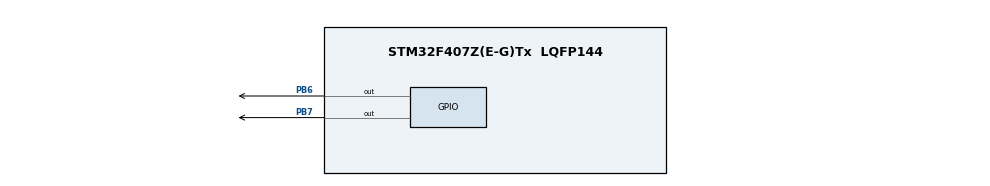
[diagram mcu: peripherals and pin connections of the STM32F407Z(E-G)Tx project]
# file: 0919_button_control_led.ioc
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Mcu.Family=STM32F4
Mcu.Name=STM32F407Z(E-G)Tx
Mcu.Package=LQFP144
NVIC.PriorityGroup=NVIC_PRIORITYGROUP_4
PA13.Mode=Serial_Wire
PA13.Signal=SYS_JTMS-SWDIO
PA14.Mode=Serial_Wire
PA14.Signal=SYS_JTCK-SWCLK
PB6.Signal=GPIO_Output
PB7.Signal=GPIO_Output
PH0-OSC_IN.Mode=HSE-External-Oscillator
PH0-OSC_IN.Signal=RCC_OSC_IN
PH1-OSC_OUT.Mode=HSE-External-Oscillator
PH1-OSC_OUT.Signal=RCC_OSC_OUT
ProjectManager.HeapSize=0x200
ProjectManager.StackSize=0x400
ProjectManager.TargetToolchain=CMake
RCC.48MHZClocksFreq_Value=84000000
RCC.AHBFreq_Value=168000000
RCC.APB1CLKDivider=RCC_HCLK_DIV4
RCC.APB1Freq_Value=42000000
RCC.APB1TimFreq_Value=84000000
RCC.APB2CLKDivider=RCC_HCLK_DIV2
RCC.APB2Freq_Value=84000000
RCC.APB2TimFreq_Value=168000000
RCC.CortexFreq_Value=168000000
RCC.HCLKFreq_Value=168000000
RCC.HSE_VALUE=8000000
RCC.HSI_VALUE=16000000
RCC.LSE_VALUE=32768
RCC.PLLM=4
RCC.PLLN=168
RCC.PLLSourceVirtual=RCC_PLLSOURCE_HSE
RCC.SYSCLKFreq_VALUE=168000000
RCC.SYSCLKSource=RCC_SYSCLKSOURCE_PLLCLK
RCC.VCOOutputFreq_Value=336000000
board=custom

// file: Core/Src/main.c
/* USER CODE BEGIN Header */
/**
  ******************************************************************************
  * @file           : main.c
  * @brief          : Main program body
  ******************************************************************************
  * @attention
  *
  * Copyright (c) 2025 STMicroelectronics.
  * All rights reserved.
  *
  * This software is licensed under terms that can be found in the LICENSE file
  * in the root directory of this software component.
  * If no LICENSE file comes with this software, it is provided AS-IS.
  *
  ******************************************************************************
  */
/* USER CODE END Header */
#include "main.h"

/* USER CODE BEGIN Includes */
#include "keys.h"
#include "oled.h"

/* USER CODE END Includes */

void SystemClock_Config(void);

/* USER CODE BEGIN 0 */
/*引脚配置*/
#define OLED_W_SCL(x)		HAL_GPIO_WritePin(GPIOB, GPIO_PIN_6, (GPIO_PinState)(x))
#define OLED_W_SDA(x)		HAL_GPIO_WritePin(GPIOB, GPIO_PIN_7, (GPIO_PinState)(x))

/*引脚初始化*/
void OLED_I2C_Init(void)
{
	__HAL_RCC_GPIOB_CLK_ENABLE();
	GPIO_InitTypeDef YuWei_GPIO_InitStructure;
 	YuWei_GPIO_InitStructure.Mode = GPIO_MODE_OUTPUT_OD;
	YuWei_GPIO_InitStructure.Speed = GPIO_SPEED_FREQ_HIGH;
	YuWei_GPIO_InitStructure.Pin = GPIO_PIN_6 | GPIO_PIN_7;
 	HAL_GPIO_Init(GPIOB, &YuWei_GPIO_InitStructure);
	OLED_W_SCL(1);
	OLED_W_SDA(1);
}

/*OLED字模库，宽8像素，高16像素*/
uint8_t OLED_F8x16[][16]=
{
	0x00,0x00,0x00,0x00,0x00,0x00,0x00,0x00,
	0x00,0x00,0x00,0x00,0x00,0x00,0x00,0x00,//  0

	0x00,0x00,0x00,0xF8,0x00,0x00,0x00,0x00,
	0x00,0x00,0x00,0x33,0x30,0x00,0x00,0x00,//! 1

	0x00,0x10,0x0C,0x06,0x10,0x0C,0x06,0x00,
	0x00,0x00,0x00,0x00,0x00,0x00,0x00,0x00,//" 2

	0x40,0xC0,0x78,0x40,0xC0,0x78,0x40,0x00,
	0x04,0x3F,0x04,0x04,0x3F,0x04,0x04,0x00,//# 3

	0x00,0x70,0x88,0xFC,0x08,0x30,0x00,0x00,
	0x00,0x18,0x20,0xFF,0x21,0x1E,0x00,0x00,//$ 4

	0xF0,0x08,0xF0,0x00,0xE0,0x18,0x00,0x00,
	0x00,0x21,0x1C,0x03,0x1E,0x21,0x1E,0x00,//% 5

	0x00,0xF0,0x08,0x88,0x70,0x00,0x00,0x00,
	0x1E,0x21,0x23,0x24,0x19,0x27,0x21,0x10,//& 6

	0x10,0x16,0x0E,0x00,0x00,0x00,0x00,0x00,
	0x00,0x00,0x00,0x00,0x00,0x00,0x00,0x00,//' 7

	0x00,0x00,0x00,0xE0,0x18,0x04,0x02,0x00,
	0x00,0x00,0x00,0x07,0x18,0x20,0x40,0x00,//( 8

	0x00,0x02,0x04,0x18,0xE0,0x00,0x00,0x00,
	0x00,0x40,0x20,0x18,0x07,0x00,0x00,0x00,//) 9

	0x40,0x40,0x80,0xF0,0x80,0x40,0x40,0x00,
	0x02,0x02,0x01,0x0F,0x01,0x02,0x02,0x00,//* 10

	0x00,0x00,0x00,0xF0,0x00,0x00,0x00,0x00,
	0x01,0x01,0x01,0x1F,0x01,0x01,0x01,0x00,//+ 11

	0x00,0x00,0x00,0x00,0x00,0x00,0x00,0x00,
	0x80,0xB0,0x70,0x00,0x00,0x00,0x00,0x00,//, 12

	0x00,0x00,0x00,0x00,0x00,0x00,0x00,0x00,
	0x00,0x01,0x01,0x01,0x01,0x01,0x01,0x01,//- 13

	0x00,0x00,0x00,0x00,0x00,0x00,0x00,0x00,
	0x00,0x30,0x30,0x00,0x00,0x00,0x00,0x00,//. 14

	0x00,0x00,0x00,0x00,0x80,0x60,0x18,0x04,
	0x00,0x60,0x18,0x06,0x01,0x00,0x00,0x00,/// 15

	0x00,0xE0,0x10,0x08,0x08,0x10,0xE0,0x00,
	0x00,0x0F,0x10,0x20,0x20,0x10,0x0F,0x00,//0 16

	0x00,0x10,0x10,0xF8,0x00,0x00,0x00,0x00,
	0x00,0x20,0x20,0x3F,0x20,0x20,0x00,0x00,//1 17

	0x00,0x70,0x08,0x08,0x08,0x88,0x70,0x00,
	0x00,0x30,0x28,0x24,0x22,0x21,0x30,0x00,//2 18

	0x00,0x30,0x08,0x88,0x88,0x48,0x30,0x00,
	0x00,0x18,0x20,0x20,0x20,0x11,0x0E,0x00,//3 19

	0x00,0x00,0xC0,0x20,0x10,0xF8,0x00,0x00,
	0x00,0x07,0x04,0x24,0x24,0x3F,0x24,0x00,//4 20

	0x00,0xF8,0x08,0x88,0x88,0x08,0x08,0x00,
	0x00,0x19,0x21,0x20,0x20,0x11,0x0E,0x00,//5 21

	0x00,0xE0,0x10,0x88,0x88,0x18,0x00,0x00,
	0x00,0x0F,0x11,0x20,0x20,0x11,0x0E,0x00,//6 22

	0x00,0x38,0x08,0x08,0xC8,0x38,0x08,0x00,
	0x00,0x00,0x00,0x3F,0x00,0x00,0x00,0x00,//7 23

	0x00,0x70,0x88,0x08,0x08,0x88,0x70,0x00,
	0x00,0x1C,0x22,0x21,0x21,0x22,0x1C,0x00,//8 24

	0x00,0xE0,0x10,0x08,0x08,0x10,0xE0,0x00,
	0x00,0x00,0x31,0x22,0x22,0x11,0x0F,0x00,//9 25

	0x00,0x00,0x00,0xC0,0xC0,0x00,0x00,0x00,
	0x00,0x00,0x00,0x30,0x30,0x00,0x00,0x00,//: 26

	0x00,0x00,0x00,0x80,0x00,0x00,0x00,0x00,
	0x00,0x00,0x80,0x60,0x00,0x00,0x00,0x00,//; 27

	0x00,0x00,0x80,0x40,0x20,0x10,0x08,0x00,
	0x00,0x01,0x02,0x04,0x08,0x10,0x20,0x00,//< 28

	0x40,0x40,0x40,0x40,0x40,0x40,0x40,0x00,
	0x04,0x04,0x04,0x04,0x04,0x04,0x04,0x00,//= 29

	0x00,0x08,0x10,0x20,0x40,0x80,0x00,0x00,
	0x00,0x20,0x10,0x08,0x04,0x02,0x01,0x00,//> 30

	0x00,0x70,0x48,0x08,0x08,0x08,0xF0,0x00,
	0x00,0x00,0x00,0x30,0x36,0x01,0x00,0x00,//? 31

	0xC0,0x30,0xC8,0x28,0xE8,0x10,0xE0,0x00,
	0x07,0x18,0x27,0x24,0x23,0x14,0x0B,0x00,//@ 32

	0x00,0x00,0xC0,0x38,0xE0,0x00,0x00,0x00,
	0x20,0x3C,0x23,0x02,0x02,0x27,0x38,0x20,//A 33

	0x08,0xF8,0x88,0x88,0x88,0x70,0x00,0x00,
	0x20,0x3F,0x20,0x20,0x20,0x11,0x0E,0x00,//B 34

	0xC0,0x30,0x08,0x08,0x08,0x08,0x38,0x00,
	0x07,0x18,0x20,0x20,0x20,0x10,0x08,0x00,//C 35

	0x08,0xF8,0x08,0x08,0x08,0x10,0xE0,0x00,
	0x20,0x3F,0x20,0x20,0x20,0x10,0x0F,0x00,//D 36

	0x08,0xF8,0x88,0x88,0xE8,0x08,0x10,0x00,
	0x20,0x3F,0x20,0x20,0x23,0x20,0x18,0x00,//E 37

	0x08,0xF8,0x88,0x88,0xE8,0x08,0x10,0x00,
	0x20,0x3F,0x20,0x00,0x03,0x00,0x00,0x00,//F 38

	0xC0,0x30,0x08,0x08,0x08,0x38,0x00,0x00,
	0x07,0x18,0x20,0x20,0x22,0x1E,0x02,0x00,//G 39

	0x08,0xF8,0x08,0x00,0x00,0x08,0xF8,0x08,
	0x20,0x3F,0x21,0x01,0x01,0x21,0x3F,0x20,//H 40

	0x00,0x08,0x08,0xF8,0x08,0x08,0x00,0x00,
	0x00,0x20,0x20,0x3F,0x20,0x20,0x00,0x00,//I 41

	0x00,0x00,0x08,0x08,0xF8,0x08,0x08,0x00,
	0xC0,0x80,0x80,0x80,0x7F,0x00,0x00,0x00,//J 42

	0x08,0xF8,0x88,0xC0,0x28,0x18,0x08,0x00,
	0x20,0x3F,0x20,0x01,0x26,0x38,0x20,0x00,//K 43

	0x08,0xF8,0x08,0x00,0x00,0x00,0x00,0x00,
	0x20,0x3F,0x20,0x20,0x20,0x20,0x30,0x00,//L 44

	0x08,0xF8,0xF8,0x00,0xF8,0xF8,0x08,0x00,
	0x20,0x3F,0x00,0x3F,0x00,0x3F,0x20,0x00,//M 45

	0x08,0xF8,0x30,0xC0,0x00,0x08,0xF8,0x08,
	0x20,0x3F,0x20,0x00,0x07,0x18,0x3F,0x00,//N 46

	0xE0,0x10,0x08,0x08,0x08,0x10,0xE0,0x00,
	0x0F,0x10,0x20,0x20,0x20,0x10,0x0F,0x00,//O 47

	0x08,0xF8,0x08,0x08,0x08,0x08,0xF0,0x00,
	0x20,0x3F,0x21,0x01,0x01,0x01,0x00,0x00,//P 48

	0xE0,0x10,0x08,0x08,0x08,0x10,0xE0,0x00,
	0x0F,0x18,0x24,0x24,0x38,0x50,0x4F,0x00,//Q 49

	0x08,0xF8,0x88,0x88,0x88,0x88,0x70,0x00,
	0x20,0x3F,0x20,0x00,0x03,0x0C,0x30,0x20,//R 50

	0x00,0x70,0x88,0x08,0x08,0x08,0x38,0x00,
	0x00,0x38,0x20,0x21,0x21,0x22,0x1C,0x00,//S 51

	0x18,0x08,0x08,0xF8,0x08,0x08,0x18,0x00,
	0x00,0x00,0x20,0x3F,0x20,0x00,0x00,0x00,//T 52

	0x08,0xF8,0x08,0x00,0x00,0x08,0xF8,0x08,
	0x00,0x1F,0x20,0x20,0x20,0x20,0x1F,0x00,//U 53

	0x08,0x78,0x88,0x00,0x00,0xC8,0x38,0x08,
	0x00,0x00,0x07,0x38,0x0E,0x01,0x00,0x00,//V 54

	0xF8,0x08,0x00,0xF8,0x00,0x08,0xF8,0x00,
	0x03,0x3C,0x07,0x00,0x07,0x3C,0x03,0x00,//W 55

	0x08,0x18,0x68,0x80,0x80,0x68,0x18,0x08,
	0x20,0x30,0x2C,0x03,0x03,0x2C,0x30,0x20,//X 56

	0x08,0x38,0xC8,0x00,0xC8,0x38,0x08,0x00,
	0x00,0x00,0x20,0x3F,0x20,0x00,0x00,0x00,//Y 57

	0x10,0x08,0x08,0x08,0xC8,0x38,0x08,0x00,
	0x20,0x38,0x26,0x21,0x20,0x20,0x18,0x00,//Z 58

	0x00,0x00,0x00,0xFE,0x02,0x02,0x02,0x00,
	0x00,0x00,0x00,0x7F,0x40,0x40,0x40,0x00,//[ 59

	0x00,0x0C,0x30,0xC0,0x00,0x00,0x00,0x00,
	0x00,0x00,0x00,0x01,0x06,0x38,0xC0,0x00,//\ 60

	0x00,0x02,0x02,0x02,0xFE,0x00,0x00,0x00,
	0x00,0x40,0x40,0x40,0x7F,0x00,0x00,0x00,//] 61

	0x00,0x00,0x04,0x02,0x02,0x02,0x04,0x00,
	0x00,0x00,0x00,0x00,0x00,0x00,0x00,0x00,//^ 62

	0x00,0x00,0x00,0x00,0x00,0x00,0x00,0x00,
	0x80,0x80,0x80,0x80,0x80,0x80,0x80,0x80,//_ 63

	0x00,0x02,0x02,0x04,0x00,0x00,0x00,0x00,
	0x00,0x00,0x00,0x00,0x00,0x00,0x00,0x00,//` 64

	0x00,0x00,0x80,0x80,0x80,0x80,0x00,0x00,
	0x00,0x19,0x24,0x22,0x22,0x22,0x3F,0x20,//a 65

	0x08,0xF8,0x00,0x80,0x80,0x00,0x00,0x00,
	0x00,0x3F,0x11,0x20,0x20,0x11,0x0E,0x00,//b 66

	0x00,0x00,0x00,0x80,0x80,0x80,0x00,0x00,
	0x00,0x0E,0x11,0x20,0x20,0x20,0x11,0x00,//c 67

	0x00,0x00,0x00,0x80,0x80,0x88,0xF8,0x00,
	0x00,0x0E,0x11,0x20,0x20,0x10,0x3F,0x20,//d 68

	0x00,0x00,0x80,0x80,0x80,0x80,0x00,0x00,
	0x00,0x1F,0x22,0x22,0x22,0x22,0x13,0x00,//e 69

	0x00,0x80,0x80,0xF0,0x88,0x88,0x88,0x18,
	0x00,0x20,0x20,0x3F,0x20,0x20,0x00,0x00,//f 70

	0x00,0x00,0x80,0x80,0x80,0x80,0x80,0x00,
	0x00,0x6B,0x94,0x94,0x94,0x93,0x60,0x00,//g 71

	0x08,0xF8,0x00,0x80,0x80,0x80,0x00,0x00,
	0x20,0x3F,0x21,0x00,0x00,0x20,0x3F,0x20,//h 72

	0x00,0x80,0x98,0x98,0x00,0x00,0x00,0x00,
	0x00,0x20,0x20,0x3F,0x20,0x20,0x00,0x00,//i 73

	0x00,0x00,0x00,0x80,0x98,0x98,0x00,0x00,
	0x00,0xC0,0x80,0x80,0x80,0x7F,0x00,0x00,//j 74

	0x08,0xF8,0x00,0x00,0x80,0x80,0x80,0x00,
	0x20,0x3F,0x24,0x02,0x2D,0x30,0x20,0x00,//k 75

	0x00,0x08,0x08,0xF8,0x00,0x00,0x00,0x00,
	0x00,0x20,0x20,0x3F,0x20,0x20,0x00,0x00,//l 76

	0x80,0x80,0x80,0x80,0x80,0x80,0x80,0x00,
	0x20,0x3F,0x20,0x00,0x3F,0x20,0x00,0x3F,//m 77

	0x80,0x80,0x00,0x80,0x80,0x80,0x00,0x00,
	0x20,0x3F,0x21,0x00,0x00,0x20,0x3F,0x20,//n 78

	0x00,0x00,0x80,0x80,0x80,0x80,0x00,0x00,
	0x00,0x1F,0x20,0x20,0x20,0x20,0x1F,0x00,//o 79

	0x80,0x80,0x00,0x80,0x80,0x00,0x00,0x00,
	0x80,0xFF,0xA1,0x20,0x20,0x11,0x0E,0x00,//p 80

	0x00,0x00,0x00,0x80,0x80,0x80,0x80,0x00,
	0x00,0x0E,0x11,0x20,0x20,0xA0,0xFF,0x80,//q 81

	0x80,0x80,0x80,0x00,0x80,0x80,0x80,0x00,
	0x20,0x20,0x3F,0x21,0x20,0x00,0x01,0x00,//r 82

	0x00,0x00,0x80,0x80,0x80,0x80,0x80,0x00,
	0x00,0x33,0x24,0x24,0x24,0x24,0x19,0x00,//s 83

	0x00,0x80,0x80,0xE0,0x80,0x80,0x00,0x00,
	0x00,0x00,0x00,0x1F,0x20,0x20,0x00,0x00,//t 84

	0x80,0x80,0x00,0x00,0x00,0x80,0x80,0x00,
	0x00,0x1F,0x20,0x20,0x20,0x10,0x3F,0x20,//u 85

	0x80,0x80,0x80,0x00,0x00,0x80,0x80,0x80,
	0x00,0x01,0x0E,0x30,0x08,0x06,0x01,0x00,//v 86

	0x80,0x80,0x00,0x80,0x00,0x80,0x80,0x80,
	0x0F,0x30,0x0C,0x03,0x0C,0x30,0x0F,0x00,//w 87

	0x00,0x80,0x80,0x00,0x80,0x80,0x80,0x00,
	0x00,0x20,0x31,0x2E,0x0E,0x31,0x20,0x00,//x 88

	0x80,0x80,0x80,0x00,0x00,0x80,0x80,0x80,
	0x80,0x81,0x8E,0x70,0x18,0x06,0x01,0x00,//y 89

	0x00,0x80,0x80,0x80,0x80,0x80,0x80,0x00,
	0x00,0x21,0x30,0x2C,0x22,0x21,0x30,0x00,//z 90

	0x00,0x00,0x00,0x00,0x80,0x7C,0x02,0x02,
	0x00,0x00,0x00,0x00,0x00,0x3F,0x40,0x40,//{ 91

	0x00,0x00,0x00,0x00,0xFF,0x00,0x00,0x00,
	0x00,0x00,0x00,0x00,0xFF,0x00,0x00,0x00,//| 92

	0x00,0x02,0x02,0x7C,0x80,0x00,0x00,0x00,
	0x00,0x40,0x40,0x3F,0x00,0x00,0x00,0x00,//} 93

	0x00,0x06,0x01,0x01,0x02,0x02,0x04,0x04,
	0x00,0x00,0x00,0x00,0x00,0x00,0x00,0x00,//~ 94
};

/**
  * @brief  I2C开始
  * @param  无
  * @retval 无
  */
void OLED_I2C_Start(void)
{
	OLED_W_SDA(1);
	OLED_W_SCL(1);
	OLED_W_SDA(0);
	OLED_W_SCL(0);
}

/**
  * @brief  I2C停止
  * @param  无
  * @retval 无
  */
void OLED_I2C_Stop(void)
{
	OLED_W_SDA(0);
	OLED_W_SCL(1);
	OLED_W_SDA(1);
}

/**
  * @brief  I2C发送一个字节
  * @param  Byte 要发送的一个字节
  * @retval 无
  */
void OLED_I2C_SendByte(uint8_t Byte)
{
	uint8_t i;
	for (i = 0; i < 8; i++)
	{
		OLED_W_SDA(Byte & (0x80 >> i));
		OLED_W_SCL(1);
		OLED_W_SCL(0);
	}
	OLED_W_SCL(1);	//额外的一个时钟，不处理应答信号
	OLED_W_SCL(0);
}

/**
  * @brief  OLED写命令
  * @param  Command 要写入的命令
  * @retval 无
  */
void OLED_WriteCommand(uint8_t Command)
{
	OLED_I2C_Start();
	OLED_I2C_SendByte(0x78);		//从机地址
	OLED_I2C_SendByte(0x00);		//写命令
	OLED_I2C_SendByte(Command);
	OLED_I2C_Stop();
}

/**
  * @brief  OLED写数据
  * @param  Data 要写入的数据
  * @retval 无
  */
void OLED_WriteData(uint8_t Data)
{
	OLED_I2C_Start();
	OLED_I2C_SendByte(0x78);		//从机地址
	OLED_I2C_SendByte(0x40);		//写数据
	OLED_I2C_SendByte(Data);
	OLED_I2C_Stop();
}

/**
  * @brief  OLED设置光标位置
  * @param  Y 以左上角为原点，向下方向的坐标，范围：0~7
  * @param  X 以左上角为原点，向右方向的坐标，范围：0~127
  * @retval 无
  */
void OLED_SetCursor(uint8_t Y, uint8_t X)
{
	OLED_WriteCommand(0xB0 | Y);					//设置Y位置
	OLED_WriteCommand(0x10 | ((X & 0xF0) >> 4));	//设置X位置低4位
	OLED_WriteCommand(0x00 | (X & 0x0F));			//设置X位置高4位
}

/**
  * @brief  OLED清屏
  * @param  无
  * @retval 无
  */
void OLED_Clear(void)
{
	uint8_t i, j;
	for (j = 0; j < 8; j++)
	{
		OLED_SetCursor(j, 0);
		for(i = 0; i < 128; i++)
		{
			OLED_WriteData(0x00);
		}
	}
}

/**
  * @brief  OLED显示一个字符
  * @param  Row 行位置，范围：1~4
  * @param  Column 列位置，范围：1~16
  * @param  Character 要显示的一个字符，范围：ASCII可见字符
  * @retval 无
  */
void OLED_ShowCharacter(uint8_t Row, uint8_t Column, char Character)
{
	uint8_t i;
	OLED_SetCursor((Row - 1) * 2, (Column - 1) * 8);			//设置光标位置在上半部分
	for (i = 0; i < 8; i++)
	{
		OLED_WriteData(OLED_F8x16[Character - ' '][i]);			//显示上半部分内容
	}
	OLED_SetCursor((Row - 1) * 2 + 1, (Column - 1) * 8);		//设置光标位置在下半部分
	for (i = 0; i < 8; i++)
	{
		OLED_WriteData(OLED_F8x16[Character - ' '][i + 8]);		//显示下半部分内容
	}
}

/**
  * @brief  OLED显示字符串
  * @param  Row 起始行位置，范围：1~4
  * @param  Column 起始列位置，范围：1~16
  * @param  String 要显示的字符串，范围：ASCII可见字符
  * @retval 无
  */
void OLED_ShowString(uint8_t Row, uint8_t Column, char *String)
{
	uint8_t i;
	for (i = 0; String[i] != '\0'; i++)
	{
		OLED_ShowCharacter(Row, Column + i, String[i]);
	}
}

typedef struct
{
	char Index[3];
	char Mask[32];
}GB16;

//宋体
//16*16大小
//逐行式，顺向（高位在前）
const GB16 OLED_F16x16[] =
{
	"余",0x80,0x80,0x40,0x20,0x50,0x48,0x44,0xC3,0x44,0x48,0x50,0x20,0x40,0x80,0x80,0x00,0x00,0x40,0x22,0x1A,0x02,0x42,0x82,0x7F,0x02,0x02,0x02,0x0A,0x12,0x60,0x00,0x00,
	"伟",0x00,0x80,0x60,0xF8,0x07,0x08,0x48,0x48,0x48,0xFF,0x48,0x48,0x48,0x48,0x08,0x00,0x01,0x00,0x00,0xFF,0x00,0x02,0x02,0x02,0x02,0xFF,0x02,0x02,0x12,0x22,0x1E,0x00,
	"●",0x00,0xE0,0xF8,0xFC,0xFC,0xFE,0xFE,0xFE,0xFE,0xFE,0xFC,0xFC,0xF8,0xE0,0x00,0x00,0x00,0x03,0x0F,0x1F,0x1F,0x3F,0x3F,0x3F,0x3F,0x3F,0x1F,0x1F,0x0F,0x03,0x00,0x00,
	"○",0x00,0xE0,0xF8,0x1C,0x04,0x06,0x02,0x02,0x02,0x06,0x04,0x1C,0xF8,0xE0,0x00,0x00,0x00,0x03,0x0F,0x1C,0x10,0x30,0x20,0x20,0x20,0x30,0x10,0x1C,0x0F,0x03,0x00,0x00,
	"·",0x00,0x00,0x00,0x00,0x00,0x00,0x00,0x00,0x00,0x00,0x00,0x00,0x00,0x00,0x00,0x00,0x00,0x00,0x00,0x00,0x00,0x00,0x00,0x03,0x03,0x00,0x00,0x00,0x00,0x00,0x00,0x00,
	"→",0x80,0x80,0x80,0x80,0x80,0x80,0x80,0x80,0x90,0xA0,0xE0,0xC0,0xC0,0x80,0x80,0x00,0x00,0x00,0x00,0x00,0x00,0x00,0x00,0x00,0x04,0x02,0x03,0x01,0x01,0x00,0x00,0x00,
	"省",0x00,0x10,0x88,0x86,0xC0,0xC0,0xA0,0xAF,0x90,0x90,0x88,0x82,0x84,0x08,0x00,0x00,0x01,0x01,0x00,0xFF,0x4A,0x4A,0x4A,0x4A,0x4A,0x4A,0x4A,0x4A,0xFF,0x00,0x00,0x00,
	"市",0x00,0x08,0x88,0x88,0x88,0x88,0x89,0xFA,0x88,0x88,0x88,0x88,0x88,0x08,0x00,0x00,0x00,0x00,0x3F,0x00,0x00,0x00,0x00,0xFF,0x00,0x00,0x10,0x20,0x1F,0x00,0x00,0x00,
	"·",0x00,0x00,0x00,0x00,0x00,0x00,0x00,0x00,0x00,0x00,0x00,0x00,0x00,0x00,0x00,0x00,0x00,0x00,0x00,0x00,0x00,0x00,0x00,0x03,0x03,0x00,0x00,0x00,0x00,0x00,0x00,0x00,
	"°",0x00,0x00,0x0C,0x12,0x12,0x0C,0x00,0x00,0x00,0x00,0x00,0x00,0x00,0x00,0x00,0x00,0x00,0x00,0x00,0x00,0x00,0x00,0x00,0x00,0x00,0x00,0x00,0x00,0x00,0x00,0x00,0x00,
	"…",0x00,0xC0,0xC0,0x00,0x00,0x00,0xC0,0xC0,0x00,0x00,0x00,0xC0,0xC0,0x00,0x00,0x00,0x00,0x00,0x00,0x00,0x00,0x00,0x00,0x00,0x00,0x00,0x00,0x00,0x00,0x00,0x00,0x00,
	"：",0x00,0x00,0x00,0x00,0x00,0x00,0x00,0x00,0x00,0x00,0x00,0x00,0x00,0x00,0x00,0x00,0x00,0x00,0x36,0x36,0x00,0x00,0x00,0x00,0x00,0x00,0x00,0x00,0x00,0x00,0x00,0x00,
	"℃",0x06,0x09,0x09,0xE6,0xF8,0x0C,0x04,0x02,0x02,0x02,0x02,0x02,0x04,0x1E,0x00,0x00,0x00,0x00,0x00,0x07,0x1F,0x30,0x20,0x40,0x40,0x40,0x40,0x40,0x20,0x10,0x00,0x00,
	"％",0x00,0x00,0x7C,0x82,0x82,0x7C,0x00,0x80,0x40,0x20,0x10,0x08,0x04,0x02,0x00,0x00,0x00,0x20,0x10,0x08,0x04,0x02,0x01,0x00,0x3E,0x41,0x41,0x3E,0x00,0x00,0x00,0x00,
	"㎡",0x00,0x10,0xE0,0x10,0x10,0xE0,0x10,0x10,0xE0,0x00,0x44,0x62,0x52,0x4C,0x00,0x00,0x00,0x00,0x0F,0x00,0x00,0x0F,0x00,0x00,0x0F,0x00,0x00,0x00,0x00,0x00,0x00,0x00,
		"陈",0x40,0x40,0x42,0xCC,0x00,0x50,0x4E,0xC8,0x48,0x7F,0xC8,0x48,0x48,0x40,0x00,0x00,0x00,0x40,0x20,0x1F,0x20,0x50,0x4C,0x43,0x40,0x40,0x4F,0x50,0x50,0x5C,0x40,0x00,
	"选",0x40,0x21,0x11,0x09,0x7D,0x4B,0x49,0x49,0x49,0x49,0x49,0x79,0x01,0x01,0x00,0x00,0x10,0x09,0xFD,0x4B,0x49,0x49,0xF9,0x10,0x09,0xFD,0x4B,0x49,0x49,0xF9,0x01,0x00,
	"磊",0x06,0x09,0x09,0xE6,0xF8,0x0C,0x04,0x02,0x02,0x02,0x02,0x02,0x04,0x1E,0x00,0x00,0x00,0x00,0x00,0x07,0x1F,0x30,0x20,0x40,0x40,0x40,0x40,0x40,0x20,0x10,0x00,0x00,
	"大",0x20,0x20,0x20,0x20,0x20,0x20,0x20,0xFF,0x20,0x20,0x20,0x20,0x20,0x20,0x20,0x00,0x80,0x80,0x40,0x20,0x10,0x0C,0x03,0x00,0x03,0x0C,0x10,0x20,0x40,0x80,0x80,0x00,/*"大",0*/
	"气",0x20,0x10,0x4C,0x47,0x54,0x54,0x54,0x54,0x54,0x54,0x54,0xD4,0x04,0x04,0x00,0x00,0x00,0x00,0x00,0x00,0x00,0x00,0x00,0x00,0x00,0x00,0x00,0x0F,0x30,0x40,0xF0,0x00,/*"气",1*/
	"温",0x10,0x60,0x02,0x8C,0x00,0x00,0xFE,0x92,0x92,0x92,0x92,0x92,0xFE,0x00,0x00,0x00,0x04,0x04,0x7E,0x01,0x40,0x7E,0x42,0x42,0x7E,0x42,0x7E,0x42,0x42,0x7E,0x40,0x00,/*"温",2*/
	"湿",0x10,0x60,0x02,0x8C,0x00,0xFE,0x92,0x92,0x92,0x92,0x92,0x92,0xFE,0x00,0x00,0x00,0x04,0x04,0x7E,0x01,0x44,0x48,0x50,0x7F,0x40,0x40,0x7F,0x50,0x48,0x44,0x40,0x00,/*"湿",3*/
	"度",0x00,0x00,0xFC,0x24,0x24,0x24,0xFC,0x25,0x26,0x24,0xFC,0x24,0x24,0x24,0x04,0x00,0x40,0x30,0x8F,0x80,0x84,0x4C,0x55,0x25,0x25,0x25,0x55,0x4C,0x80,0x80,0x80,0x00,/*"度",4*/
	"光",0x40,0x40,0x42,0x44,0x58,0xC0,0x40,0x7F,0x40,0xC0,0x50,0x48,0x46,0x40,0x40,0x00,0x80,0x80,0x40,0x20,0x18,0x07,0x00,0x00,0x00,0x3F,0x40,0x40,0x40,0x40,0x78,0x00,/*"光",5*/
	"照",0x00,0xFE,0x42,0x42,0x42,0xFE,0x00,0x42,0xA2,0x9E,0x82,0xA2,0xC2,0xBE,0x00,0x00,0x80,0x6F,0x08,0x08,0x28,0xCF,0x00,0x00,0x2F,0xC8,0x08,0x08,0x28,0xCF,0x00,0x00,/*"照",6*/
	"强",0x02,0xE2,0x22,0x22,0x3E,0x00,0x80,0x9E,0x92,0x92,0xF2,0x92,0x92,0x9E,0x80,0x00,0x00,0x43,0x82,0x42,0x3E,0x40,0x47,0x44,0x44,0x44,0x7F,0x44,0x44,0x54,0xE7,0x00,/*"强",7*/
	"度",0x00,0x00,0xFC,0x24,0x24,0x24,0xFC,0x25,0x26,0x24,0xFC,0x24,0x24,0x24,0x04,0x00,0x40,0x30,0x8F,0x80,0x84,0x4C,0x55,0x25,0x25,0x25,0x55,0x4C,0x80,0x80,0x80,0x00,/*"度",8*/
	"紫",0x20,0x20,0x3E,0x20,0x1F,0x94,0x54,0x00,0x1F,0x24,0xA4,0x24,0x22,0x38,0x00,0x00,0x00,0x80,0x48,0x29,0x09,0x4D,0x8D,0x7B,0x0B,0x09,0x28,0x4C,0x98,0x00,0x00,0x00,/*"紫",9*/
	"外",0x00,0xC0,0x30,0x1F,0x10,0x10,0xF0,0x00,0x00,0xFF,0x20,0x40,0x80,0x00,0x00,0x00,0x81,0x40,0x21,0x12,0x0C,0x03,0x00,0x00,0x00,0xFF,0x00,0x00,0x00,0x03,0x00,0x00,/*"外",10*/
	"线",0x20,0x30,0xAC,0x63,0x20,0x18,0x80,0x90,0x90,0xFF,0x90,0x49,0x4A,0x48,0x40,0x00,0x22,0x67,0x22,0x12,0x12,0x12,0x40,0x40,0x20,0x13,0x0C,0x14,0x22,0x41,0xF8,0x00,/*"线",11*/
	"线",0x20,0x30,0xAC,0x63,0x20,0x18,0x80,0x90,0x90,0xFF,0x90,0x49,0x4A,0x48,0x40,0x00,0x22,0x67,0x22,0x12,0x12,0x12,0x40,0x40,0x20,0x13,0x0C,0x14,0x22,0x41,0xF8,0x00,/*"线",12*/
	"加",0x10,0x10,0x10,0xFF,0x10,0x10,0xF0,0x00,0x00,0xF8,0x08,0x08,0x08,0xF8,0x00,0x00,0x80,0x40,0x30,0x0F,0x40,0x80,0x7F,0x00,0x00,0x7F,0x20,0x20,0x20,0x7F,0x00,0x00,/*"加",13*/
	"轴",0xC8,0xB8,0x8F,0xE8,0x88,0x88,0x00,0xF0,0x10,0x10,0xFF,0x10,0x10,0xF0,0x00,0x00,0x08,0x18,0x08,0xFF,0x04,0x04,0x00,0xFF,0x42,0x42,0x7F,0x42,0x42,0xFF,0x00,0x00,/*"轴",14*/
	"速",0x40,0x40,0x42,0xCC,0x00,0x04,0xF4,0x94,0x94,0xFF,0x94,0x94,0xF4,0x04,0x00,0x00,0x00,0x40,0x20,0x1F,0x20,0x48,0x44,0x42,0x41,0x5F,0x41,0x42,0x44,0x48,0x40,0x00,/*"速",15*/
	"度",0x00,0x00,0xFC,0x24,0x24,0x24,0xFC,0x25,0x26,0x24,0xFC,0x24,0x24,0x24,0x04,0x00,0x40,0x30,0x8F,0x80,0x84,0x4C,0x55,0x25,0x25,0x25,0x55,0x4C,0x80,0x80,0x80,0x00,/*"度",16*/
	"姿",0x20,0x21,0xF2,0x08,0x04,0x10,0x88,0x84,0x47,0x34,0x44,0x84,0x94,0x0C,0x00,0x00,0x04,0x84,0x85,0x94,0x5D,0x57,0x24,0x24,0x24,0x54,0x4C,0x44,0x84,0x05,0x05,0x00,/*"姿",17*/
	"态",0x00,0x04,0x84,0x84,0x44,0x24,0x54,0x8F,0x14,0x24,0x44,0x84,0x84,0x04,0x00,0x00,0x41,0x39,0x00,0x00,0x3C,0x40,0x40,0x42,0x4C,0x40,0x40,0x70,0x04,0x09,0x31,0x00,/*"态",18*/
	"角",0x20,0x10,0xE8,0x24,0x27,0x24,0x24,0xE4,0x24,0x34,0x2C,0x20,0xE0,0x00,0x00,0x00,0x80,0x60,0x1F,0x09,0x09,0x09,0x09,0x7F,0x09,0x09,0x49,0x89,0x7F,0x00,0x00,0x00,/*"角",19*/
	"欧",0x00,0xFE,0x12,0x22,0xC2,0x3A,0x02,0x40,0x30,0x0F,0xC8,0x08,0x28,0x18,0x00,0x00,0x00,0x3F,0x24,0x23,0x20,0x27,0xA0,0x40,0x30,0x0E,0x01,0x0E,0x30,0x40,0x80,0x00,/*"欧",20*/
	"拉",0x10,0x10,0x10,0xFF,0x90,0x40,0x10,0x90,0x10,0x11,0x16,0x10,0x10,0xD0,0x10,0x00,0x02,0x42,0x81,0x7F,0x00,0x40,0x40,0x41,0x5E,0x40,0x40,0x70,0x4E,0x41,0x40,0x00,/*"拉",21*/
	"四",0x00,0xFC,0x04,0x04,0x04,0xFC,0x04,0x04,0x04,0xFC,0x04,0x04,0x04,0xFC,0x00,0x00,0x00,0x7F,0x28,0x24,0x23,0x20,0x20,0x20,0x20,0x21,0x22,0x22,0x22,0x7F,0x00,0x00,/*"四",22*/
	"元",0x20,0x20,0x22,0x22,0x22,0xE2,0x22,0x22,0x22,0xE2,0x22,0x22,0x22,0x20,0x20,0x00,0x80,0x40,0x20,0x10,0x0C,0x03,0x00,0x00,0x00,0x3F,0x40,0x40,0x40,0x40,0x78,0x00,/*"元",23*/
	"数",0x90,0x52,0x34,0x10,0xFF,0x10,0x34,0x52,0x80,0x70,0x8F,0x08,0x08,0xF8,0x08,0x00,0x82,0x9A,0x56,0x63,0x22,0x52,0x8E,0x00,0x80,0x40,0x33,0x0C,0x33,0x40,0x80,0x00,/*"数",24*/
	"俯",0x80,0x60,0xF8,0x07,0x00,0xFC,0x04,0xC4,0x34,0x85,0x86,0x84,0xF4,0x84,0x84,0x00,0x00,0x00,0xFF,0x40,0x30,0x0F,0x01,0xFF,0x00,0x02,0x4C,0x80,0x7F,0x00,0x00,0x00,/*"俯",25*/
	"仰",0x00,0x80,0x60,0xF8,0x07,0x00,0xFC,0x04,0x02,0x00,0xFC,0x04,0x04,0xFC,0x00,0x00,0x01,0x00,0x00,0xFF,0x00,0x00,0x1F,0x08,0x04,0x00,0xFF,0x04,0x08,0x07,0x00,0x00,/*"仰",26*/
	"翻",0x96,0x5A,0x32,0x7E,0x31,0x59,0x95,0x12,0x22,0xFE,0x00,0x12,0x22,0xFE,0x00,0x00,0x00,0xFF,0x49,0x7F,0x49,0xFF,0x00,0x44,0x82,0x7F,0x04,0x42,0x81,0x7F,0x00,0x00,/*"翻",27*/
	"滚",0x10,0x60,0x02,0x8C,0x00,0x24,0x94,0xCC,0xA5,0x96,0xC4,0x8C,0x14,0x24,0x00,0x00,0x04,0x04,0x7E,0x01,0x20,0x10,0x08,0xFC,0x42,0x24,0x08,0x15,0x22,0x40,0x40,0x00,/*"滚",0*/
	"偏",0x80,0x60,0xF8,0x07,0x00,0xFC,0x24,0x24,0x25,0x26,0x24,0x24,0x24,0x3C,0x00,0x00,0x00,0x00,0xFF,0x40,0x3C,0x03,0xFF,0x09,0x7F,0x09,0x7F,0x09,0x89,0xFF,0x00,0x00,/*"偏",1*/
	"航",0x80,0xFC,0x96,0xE5,0x84,0xFC,0x00,0x08,0xC8,0x49,0x4A,0xC8,0x08,0x08,0x00,0x00,0x80,0x7F,0x02,0x4C,0x80,0x7F,0x80,0x60,0x1F,0x00,0x00,0x3F,0x40,0x40,0x78,0x00,/*"航",2*/
	"正",0x00,0x02,0x02,0xC2,0x02,0x02,0x02,0xFE,0x82,0x82,0x82,0x82,0x82,0x02,0x00,0x00,0x40,0x40,0x40,0x7F,0x40,0x40,0x40,0x7F,0x40,0x40,0x40,0x40,0x40,0x40,0x40,0x00,/*"正",3*/
	"在",0x08,0x08,0x88,0xC8,0x38,0x0C,0x0B,0x08,0x08,0xE8,0x08,0x08,0x08,0x08,0x08,0x00,0x02,0x01,0x00,0xFF,0x40,0x41,0x41,0x41,0x41,0x7F,0x41,0x41,0x41,0x41,0x40,0x00,/*"在",4*/
	"初",0x08,0x08,0x89,0xEA,0x18,0x88,0x00,0x04,0x04,0xFC,0x04,0x04,0x04,0xFC,0x00,0x00,0x02,0x01,0x00,0xFF,0x01,0x86,0x40,0x20,0x18,0x07,0x40,0x80,0x40,0x3F,0x00,0x00,/*"初",5*/
	"始",0x10,0x10,0xF0,0x1F,0x10,0xF0,0x00,0x40,0xE0,0x58,0x47,0x40,0x50,0x60,0xC0,0x00,0x40,0x22,0x15,0x08,0x16,0x21,0x00,0x00,0xFE,0x42,0x42,0x42,0x42,0xFE,0x00,0x00,/*"始",6*/
	"化",0x00,0x80,0x60,0xF8,0x07,0x00,0x00,0x00,0xFF,0x40,0x20,0x10,0x08,0x04,0x00,0x00,0x01,0x00,0x00,0xFF,0x00,0x04,0x02,0x01,0x3F,0x40,0x40,0x40,0x40,0x40,0x78,0x00,/*"化",7*/
	"中",0x00,0x00,0xF0,0x10,0x10,0x10,0x10,0xFF,0x10,0x10,0x10,0x10,0xF0,0x00,0x00,0x00,0x00,0x00,0x0F,0x04,0x04,0x04,0x04,0xFF,0x04,0x04,0x04,0x04,0x0F,0x00,0x00,0x00,/*"中",8*/
	"毕",0x00,0x00,0xFF,0x88,0x88,0x48,0x48,0x00,0x7F,0x88,0x84,0x84,0x82,0xE0,0x00,0x00,0x04,0x04,0x05,0x04,0x04,0x04,0x04,0xFF,0x04,0x04,0x04,0x04,0x04,0x04,0x04,0x00,/*"毕",9*/
	"向",0x00,0xF8,0x08,0x08,0x0C,0xCA,0x49,0x48,0x48,0xC8,0x08,0x08,0x08,0xF8,0x00,0x00,0x00,0xFF,0x00,0x00,0x00,0x1F,0x08,0x08,0x08,0x1F,0x00,0x40,0x80,0x7F,0x00,0x00,/*"向",10*/
	"上",0x00,0x00,0x00,0x00,0x00,0x00,0xFF,0x40,0x40,0x40,0x40,0x40,0x40,0x00,0x00,0x00,0x40,0x40,0x40,0x40,0x40,0x40,0x7F,0x40,0x40,0x40,0x40,0x40,0x40,0x40,0x40,0x00,/*"上",11*/
	"下",0x02,0x02,0x02,0x02,0x02,0x02,0xFE,0x02,0x02,0x42,0x82,0x02,0x02,0x02,0x02,0x00,0x00,0x00,0x00,0x00,0x00,0x00,0xFF,0x00,0x00,0x00,0x00,0x01,0x06,0x00,0x00,0x00,/*"下",12*/
	"左",0x08,0x08,0x08,0x08,0x88,0x78,0x0F,0x08,0x08,0x08,0x08,0x08,0x08,0x08,0x08,0x00,0x20,0x10,0x48,0x46,0x41,0x41,0x41,0x41,0x7F,0x41,0x41,0x41,0x41,0x40,0x40,0x00,/*"左",13*/
	"右",0x08,0x08,0x08,0x08,0xC8,0x38,0x0F,0x08,0x08,0x08,0x08,0x08,0x08,0x08,0x08,0x00,0x08,0x04,0x02,0x01,0xFF,0x41,0x41,0x41,0x41,0x41,0x41,0x41,0xFF,0x00,0x00,0x00,/*"右",14*/
	"前",0x08,0x08,0xE8,0x29,0x2E,0x28,0xE8,0x08,0x08,0xC8,0x0C,0x0B,0xE8,0x08,0x08,0x00,0x00,0x00,0xFF,0x09,0x49,0x89,0x7F,0x00,0x00,0x0F,0x40,0x80,0x7F,0x00,0x00,0x00,/*"前",15*/
	"后",0x00,0x00,0x00,0xFC,0x24,0x24,0x24,0x24,0x22,0x22,0x22,0x23,0x22,0x20,0x20,0x00,0x40,0x20,0x18,0x07,0x00,0xFE,0x42,0x42,0x42,0x42,0x42,0x42,0xFE,0x00,0x00,0x00,/*"后",16*/
	"挥",0x10,0x10,0x10,0xFF,0x10,0x98,0x26,0x22,0xE2,0x3A,0xA2,0x22,0x22,0x2A,0x06,0x00,0x04,0x44,0x82,0x7F,0x01,0x10,0x10,0x13,0x12,0x12,0xFF,0x12,0x12,0x12,0x10,0x00,/*"挥",17*/
	"动",0x40,0x44,0xC4,0x44,0x44,0x44,0x40,0x10,0x10,0xFF,0x10,0x10,0x10,0xF0,0x00,0x00,0x10,0x3C,0x13,0x10,0x14,0xB8,0x40,0x30,0x0E,0x01,0x40,0x80,0x40,0x3F,0x00,0x00,/*"动",18*/
	"无",0x00,0x40,0x42,0x42,0x42,0xC2,0x7E,0x42,0xC2,0x42,0x42,0x42,0x40,0x40,0x00,0x00,0x80,0x40,0x20,0x10,0x0C,0x03,0x00,0x00,0x3F,0x40,0x40,0x40,0x40,0x70,0x00,0x00,/*"无",19*/
	"有",0x04,0x04,0x04,0x84,0xE4,0x3C,0x27,0x24,0x24,0x24,0x24,0xE4,0x04,0x04,0x04,0x00,0x04,0x02,0x01,0x00,0xFF,0x09,0x09,0x09,0x09,0x49,0x89,0x7F,0x00,0x00,0x00,0x00,/*"有",20*/
	"手",0x00,0x00,0x24,0x24,0x24,0x24,0x24,0xFC,0x22,0x22,0x22,0x23,0x22,0x00,0x00,0x00,0x02,0x02,0x02,0x02,0x02,0x42,0x82,0x7F,0x02,0x02,0x02,0x02,0x02,0x02,0x02,0x00,/*"手",21*/
	"势",0x00,0x44,0x44,0x24,0xFF,0x14,0x00,0x24,0xA4,0x7F,0x84,0x04,0xFC,0x00,0xC0,0x00,0x00,0x88,0x89,0x4A,0x29,0x18,0x0E,0x0A,0x09,0x48,0x88,0x48,0x38,0x01,0x03,0x00,/*"势",22*/
	"·",0x00,0x00,0x00,0x00,0x00,0x00,0x00,0x00,0x00,0x00,0x00,0x00,0x00,0x00,0x00,0x00,0x00,0x00,0x00,0x00,0x00,0x00,0x00,0x03,0x03,0x00,0x00,0x00,0x00,0x00,0x00,0x00,/*"·",0*/
	"°",0x00,0x00,0x0C,0x12,0x12,0x0C,0x00,0x00,0x00,0x00,0x00,0x00,0x00,0x00,0x00,0x00,0x00,0x00,0x00,0x00,0x00,0x00,0x00,0x00,0x00,0x00,0x00,0x00,0x00,0x00,0x00,0x00,/*"°",1*/
	"…",0x00,0xC0,0xC0,0x00,0x00,0x00,0xC0,0xC0,0x00,0x00,0x00,0xC0,0xC0,0x00,0x00,0x00,0x00,0x00,0x00,0x00,0x00,0x00,0x00,0x00,0x00,0x00,0x00,0x00,0x00,0x00,0x00,0x00,/*"…",2*/
	"：",0x00,0x00,0x00,0x00,0x00,0x00,0x00,0x00,0x00,0x00,0x00,0x00,0x00,0x00,0x00,0x00,0x00,0x00,0x36,0x36,0x00,0x00,0x00,0x00,0x00,0x00,0x00,0x00,0x00,0x00,0x00,0x00,/*"：",3*/
	"℃",0x06,0x09,0x09,0xE6,0xF8,0x0C,0x04,0x02,0x02,0x02,0x02,0x02,0x04,0x1E,0x00,0x00,0x00,0x00,0x00,0x07,0x1F,0x30,0x20,0x40,0x40,0x40,0x40,0x40,0x20,0x10,0x00,0x00,/*"℃",4*/
	"％",0x00,0x00,0x7C,0x82,0x82,0x7C,0x00,0x80,0x40,0x20,0x10,0x08,0x04,0x02,0x00,0x00,0x00,0x20,0x10,0x08,0x04,0x02,0x01,0x00,0x3E,0x41,0x41,0x3E,0x00,0x00,0x00,0x00,/*"％",5*/
	"㎡",0x00,0x10,0xE0,0x10,0x10,0xE0,0x10,0x10,0xE0,0x00,0x44,0x62,0x52,0x4C,0x00,0x00,0x00,0x00,0x0F,0x00,0x00,0x0F,0x00,0x00,0x0F,0x00,0x00,0x00,0x00,0x00,0x00,0x00,/*"㎡",6*/
	"河",0x10,0x60,0x02,0x8C,0x00,0x04,0xE4,0x24,0x24,0xE4,0x04,0x04,0xFC,0x04,0x04,0x00,0x04,0x04,0x7E,0x01,0x00,0x00,0x0F,0x04,0x04,0x0F,0x40,0x80,0x7F,0x00,0x00,0x00,/*"河",0*/
	"北",0x00,0x20,0x20,0x20,0x20,0xFF,0x00,0x00,0x00,0xFF,0x40,0x20,0x10,0x08,0x00,0x00,0x20,0x60,0x20,0x10,0x10,0xFF,0x00,0x00,0x00,0x3F,0x40,0x40,0x40,0x40,0x78,0x00,/*"北",1*/
	"省",0x00,0x10,0x88,0x86,0xC0,0xC0,0xA0,0xAF,0x90,0x90,0x88,0x82,0x84,0x08,0x00,0x00,0x01,0x01,0x00,0xFF,0x4A,0x4A,0x4A,0x4A,0x4A,0x4A,0x4A,0x4A,0xFF,0x00,0x00,0x00,/*"省",2*/
	"冀",0x10,0x12,0xF2,0xAA,0xAA,0xBF,0xA0,0xE0,0xA0,0xA7,0xAA,0xAA,0xEA,0x09,0x0C,0x00,0x20,0x20,0xAB,0x6A,0x2A,0x3E,0x2A,0x2B,0x2A,0x3E,0x2A,0x6A,0xAB,0x20,0x20,0x00,/*"冀",3*/
	"山",0x00,0x00,0xF0,0x00,0x00,0x00,0x00,0xFF,0x00,0x00,0x00,0x00,0xF0,0x00,0x00,0x00,0x00,0x00,0x3F,0x20,0x20,0x20,0x20,0x3F,0x20,0x20,0x20,0x20,0x7F,0x00,0x00,0x00,/*"山",5*/
	"西",0x02,0x02,0xE2,0x22,0x22,0xFE,0x22,0x22,0x22,0xFE,0x22,0x22,0xE2,0x02,0x02,0x00,0x00,0x00,0xFF,0x48,0x44,0x43,0x40,0x40,0x40,0x43,0x44,0x44,0xFF,0x00,0x00,0x00,/*"西",6*/
	"省",0x00,0x10,0x88,0x86,0xC0,0xC0,0xA0,0xAF,0x90,0x90,0x88,0x82,0x84,0x08,0x00,0x00,0x01,0x01,0x00,0xFF,0x4A,0x4A,0x4A,0x4A,0x4A,0x4A,0x4A,0x4A,0xFF,0x00,0x00,0x00,/*"省",7*/
	"晋",0x40,0x42,0x4A,0x52,0x42,0x7E,0x42,0x42,0x42,0x7E,0x42,0x52,0x4A,0x42,0x40,0x00,0x00,0x00,0x00,0xFF,0x49,0x49,0x49,0x49,0x49,0x49,0x49,0xFF,0x00,0x00,0x00,0x00,/*"晋",8*/
	"辽",0x40,0x40,0x42,0xCC,0x00,0x00,0x02,0x02,0x02,0xF2,0x0A,0x06,0x02,0x00,0x00,0x00,0x00,0x40,0x20,0x1F,0x20,0x40,0x40,0x48,0x50,0x4F,0x40,0x40,0x40,0x40,0x40,0x00,/*"辽",10*/
	"宁",0x20,0x18,0x88,0x88,0x88,0x88,0x89,0x8E,0x88,0x88,0x88,0x88,0x88,0x28,0x18,0x00,0x00,0x00,0x00,0x00,0x00,0x40,0x80,0x7F,0x00,0x00,0x00,0x00,0x00,0x00,0x00,0x00,/*"宁",11*/
	"省",0x00,0x10,0x88,0x86,0xC0,0xC0,0xA0,0xAF,0x90,0x90,0x88,0x82,0x84,0x08,0x00,0x00,0x01,0x01,0x00,0xFF,0x4A,0x4A,0x4A,0x4A,0x4A,0x4A,0x4A,0x4A,0xFF,0x00,0x00,0x00,/*"省",12*/
	"辽",0x40,0x40,0x42,0xCC,0x00,0x00,0x02,0x02,0x02,0xF2,0x0A,0x06,0x02,0x00,0x00,0x00,0x00,0x40,0x20,0x1F,0x20,0x40,0x40,0x48,0x50,0x4F,0x40,0x40,0x40,0x40,0x40,0x00,/*"辽",13*/
	"吉",0x08,0x08,0x88,0x88,0x88,0x88,0x88,0xFF,0x88,0x88,0x88,0x88,0x88,0x08,0x08,0x00,0x00,0x00,0x00,0xFC,0x44,0x44,0x44,0x44,0x44,0x44,0x44,0xFC,0x00,0x00,0x00,0x00,/*"吉",15*/
	"林",0x10,0x10,0xD0,0xFF,0x90,0x10,0x00,0x10,0x10,0xD0,0xFF,0xD0,0x10,0x10,0x10,0x00,0x04,0x03,0x00,0xFF,0x00,0x11,0x08,0x04,0x03,0x00,0xFF,0x00,0x03,0x04,0x08,0x00,/*"林",16*/
	"省",0x00,0x10,0x88,0x86,0xC0,0xC0,0xA0,0xAF,0x90,0x90,0x88,0x82,0x84,0x08,0x00,0x00,0x01,0x01,0x00,0xFF,0x4A,0x4A,0x4A,0x4A,0x4A,0x4A,0x4A,0x4A,0xFF,0x00,0x00,0x00,/*"省",17*/
	"吉",0x08,0x08,0x88,0x88,0x88,0x88,0x88,0xFF,0x88,0x88,0x88,0x88,0x88,0x08,0x08,0x00,0x00,0x00,0x00,0xFC,0x44,0x44,0x44,0x44,0x44,0x44,0x44,0xFC,0x00,0x00,0x00,0x00,/*"吉",18*/
	"黑",0x00,0x00,0x3E,0x22,0x2A,0x32,0x22,0xFE,0x22,0x32,0x2A,0x22,0x3E,0x00,0x00,0x00,0x88,0x68,0x09,0x09,0x29,0xC9,0x09,0x0F,0x29,0xC9,0x09,0x09,0x29,0xC8,0x08,0x00,/*"黑",20*/
	"龙",0x10,0x10,0x10,0x10,0x10,0xFF,0x10,0x10,0xF0,0x10,0x11,0x16,0xD0,0x10,0x10,0x00,0x80,0x40,0x20,0x18,0x06,0x41,0x20,0x10,0x3F,0x44,0x42,0x41,0x40,0x40,0x78,0x00,/*"龙",21*/
	"江",0x10,0x60,0x02,0x0C,0xC0,0x04,0x04,0x04,0x04,0xFC,0x04,0x04,0x04,0x04,0x00,0x00,0x04,0x04,0x7C,0x03,0x20,0x20,0x20,0x20,0x20,0x3F,0x20,0x20,0x20,0x20,0x20,0x00,/*"江",22*/
	"苏",0x04,0x44,0x44,0x44,0x5F,0x44,0xF4,0x44,0x44,0x44,0x5F,0xC4,0x04,0x04,0x04,0x00,0x00,0x10,0x8E,0x40,0x20,0x18,0x07,0x00,0x40,0x80,0x40,0x3F,0x00,0x01,0x0E,0x00,/*"苏",27*/
	"浙",0x20,0xC2,0x0C,0x80,0x10,0x10,0xFF,0x10,0x90,0xFC,0x44,0x42,0xC3,0x42,0x40,0x00,0x04,0x04,0x7E,0x01,0x42,0x82,0x7F,0x81,0x40,0x3F,0x00,0x00,0xFF,0x00,0x00,0x00,/*"浙",31*/
	"安",0x80,0x90,0x8C,0x84,0x84,0x84,0xF5,0x86,0x84,0x84,0x84,0x84,0x94,0x8C,0x80,0x00,0x00,0x80,0x80,0x84,0x46,0x49,0x28,0x10,0x10,0x2C,0x23,0x40,0x80,0x00,0x00,0x00,/*"安",0*/
	"徽",0x10,0x88,0xC4,0x23,0xAE,0x68,0x2F,0x28,0xAE,0x20,0xD8,0x17,0x10,0xF0,0x10,0x00,0x01,0x00,0xFF,0x48,0x29,0x8D,0xFB,0x09,0xAC,0x48,0x37,0x08,0x36,0x41,0x80,0x00,/*"徽",1*/
	"皖",0x00,0xF8,0x0C,0x0B,0xF8,0x10,0x0C,0x24,0x24,0x25,0x26,0x24,0x24,0x14,0x0C,0x00,0x00,0x7F,0x21,0x21,0x7F,0x80,0x41,0x31,0x0F,0x01,0x01,0x3F,0x41,0x41,0x71,0x00,/*"皖",2*/
	"福",0x08,0x09,0xCE,0xB8,0x08,0x00,0x02,0x7A,0x4A,0x4A,0x4A,0x4A,0x4A,0x7A,0x02,0x00,0x02,0x01,0xFF,0x00,0x03,0x00,0xFF,0x49,0x49,0x49,0x7F,0x49,0x49,0x49,0xFF,0x00,/*"福",4*/
	"建",0x04,0x84,0xC4,0xB4,0x8C,0x10,0x54,0x54,0x54,0xFF,0x54,0x54,0x7C,0x10,0x10,0x00,0x80,0x44,0x28,0x18,0x27,0x28,0x49,0x49,0x49,0x7F,0x49,0x49,0x49,0x48,0x40,0x00,/*"建",5*/
	"闽",0x00,0xF8,0x01,0x02,0xE0,0x22,0x22,0xFA,0x22,0x22,0xE2,0x02,0x02,0xFE,0x00,0x00,0x00,0xFF,0x00,0x20,0x67,0x22,0x22,0x1F,0x12,0x12,0x1B,0x30,0x80,0xFF,0x00,0x00,/*"闽",6*/
	"江",0x10,0x60,0x02,0x0C,0xC0,0x04,0x04,0x04,0x04,0xFC,0x04,0x04,0x04,0x04,0x00,0x00,0x04,0x04,0x7C,0x03,0x20,0x20,0x20,0x20,0x20,0x3F,0x20,0x20,0x20,0x20,0x20,0x00,/*"江",8*/
	"西",0x02,0x02,0xE2,0x22,0x22,0xFE,0x22,0x22,0x22,0xFE,0x22,0x22,0xE2,0x02,0x02,0x00,0x00,0x00,0xFF,0x48,0x44,0x43,0x40,0x40,0x40,0x43,0x44,0x44,0xFF,0x00,0x00,0x00,/*"西",9*/
	"赣",0x12,0xD6,0x5A,0x53,0x5A,0xD6,0x12,0x28,0x64,0x57,0xCA,0x56,0x52,0x20,0x20,0x00,0x10,0x17,0x15,0xFD,0x15,0x17,0x10,0x81,0xBD,0x45,0x35,0x45,0xBD,0x01,0x00,0x00,/*"赣",10*/
	"山",0x00,0x00,0xF0,0x00,0x00,0x00,0x00,0xFF,0x00,0x00,0x00,0x00,0xF0,0x00,0x00,0x00,0x00,0x00,0x3F,0x20,0x20,0x20,0x20,0x3F,0x20,0x20,0x20,0x20,0x7F,0x00,0x00,0x00,/*"山",12*/
	"东",0x00,0x08,0x88,0x48,0x28,0x18,0x0F,0xE8,0x08,0x08,0x08,0x08,0x08,0x08,0x00,0x00,0x00,0x20,0x11,0x09,0x05,0x41,0x81,0x7F,0x01,0x01,0x05,0x09,0x11,0x20,0x00,0x00,/*"东",13*/
	"鲁",0x10,0x08,0xFC,0xAA,0xAB,0xAA,0xAA,0xFA,0xAA,0xAA,0xAE,0xA8,0xF8,0x00,0x00,0x00,0x02,0x02,0x02,0xFA,0xAA,0xAA,0xAA,0xAA,0xAA,0xAA,0xAA,0xFA,0x02,0x02,0x02,0x00,/*"鲁",14*/
	"河",0x10,0x60,0x02,0x8C,0x00,0x04,0xE4,0x24,0x24,0xE4,0x04,0x04,0xFC,0x04,0x04,0x00,0x04,0x04,0x7E,0x01,0x00,0x00,0x0F,0x04,0x04,0x0F,0x40,0x80,0x7F,0x00,0x00,0x00,/*"河",16*/
	"南",0x04,0xE4,0x24,0x24,0x64,0xA4,0x24,0x3F,0x24,0xA4,0x64,0x24,0x24,0xE4,0x04,0x00,0x00,0xFF,0x00,0x08,0x09,0x09,0x09,0x7F,0x09,0x09,0x09,0x48,0x80,0x7F,0x00,0x00,/*"南",17*/
	"豫",0x42,0x4A,0xD2,0x6A,0x46,0xD0,0x08,0x7C,0x4B,0xCA,0x6A,0x5A,0x4E,0x48,0x78,0x00,0x40,0x80,0x7F,0x00,0x01,0x00,0x4A,0x4A,0x25,0x52,0x89,0x7E,0x04,0x1A,0x21,0x00,/*"豫",18*/
	"湖",0x10,0x60,0x02,0x8C,0x00,0x88,0x88,0xFF,0x88,0x88,0x00,0xFE,0x22,0x22,0xFE,0x00,0x04,0x04,0x7E,0x01,0x00,0x1F,0x08,0x08,0x08,0x9F,0x60,0x1F,0x42,0x82,0x7F,0x00,/*"湖",20*/
	"北",0x00,0x20,0x20,0x20,0x20,0xFF,0x00,0x00,0x00,0xFF,0x40,0x20,0x10,0x08,0x00,0x00,0x20,0x60,0x20,0x10,0x10,0xFF,0x00,0x00,0x00,0x3F,0x40,0x40,0x40,0x40,0x78,0x00,/*"北",21*/
	"鄂",0x00,0x5E,0x52,0x5E,0x40,0x5E,0x52,0x5E,0x00,0x00,0xFE,0x02,0x22,0xDA,0x06,0x00,0x01,0x01,0x07,0x05,0x45,0x85,0x45,0x3D,0x01,0x00,0xFF,0x08,0x10,0x08,0x07,0x00,/*"鄂",22*/
	"湖",0x10,0x60,0x02,0x8C,0x00,0x88,0x88,0xFF,0x88,0x88,0x00,0xFE,0x22,0x22,0xFE,0x00,0x04,0x04,0x7E,0x01,0x00,0x1F,0x08,0x08,0x08,0x9F,0x60,0x1F,0x42,0x82,0x7F,0x00,/*"湖",24*/
	"南",0x04,0xE4,0x24,0x24,0x64,0xA4,0x24,0x3F,0x24,0xA4,0x64,0x24,0x24,0xE4,0x04,0x00,0x00,0xFF,0x00,0x08,0x09,0x09,0x09,0x7F,0x09,0x09,0x09,0x48,0x80,0x7F,0x00,0x00,/*"南",25*/
	"湘",0x20,0xC2,0x0C,0x80,0x10,0x90,0xFF,0x90,0x00,0xFC,0x44,0x44,0x44,0xFC,0x00,0x00,0x04,0x04,0x7E,0x05,0x02,0x01,0xFF,0x00,0x01,0xFF,0x44,0x44,0x44,0xFF,0x00,0x00,/*"湘",26*/
	"广",0x00,0x00,0xF8,0x08,0x08,0x08,0x08,0x09,0x0E,0x08,0x08,0x08,0x08,0x08,0x00,0x00,0x80,0x60,0x1F,0x00,0x00,0x00,0x00,0x00,0x00,0x00,0x00,0x00,0x00,0x00,0x00,0x00,/*"广",28*/
	"东",0x00,0x08,0x88,0x48,0x28,0x18,0x0F,0xE8,0x08,0x08,0x08,0x08,0x08,0x08,0x00,0x00,0x00,0x20,0x11,0x09,0x05,0x41,0x81,0x7F,0x01,0x01,0x05,0x09,0x11,0x20,0x00,0x00,/*"东",29*/
	"粤",0x00,0x00,0xFE,0x02,0x96,0x5A,0x33,0xFE,0x32,0x5A,0x96,0x02,0xFE,0x00,0x00,0x00,0x04,0x04,0x05,0x1D,0x15,0x15,0x15,0x15,0x15,0x55,0x95,0x55,0x35,0x04,0x04,0x00,/*"粤",30*/
	"海",0x10,0x60,0x02,0x0C,0xC0,0x10,0x08,0xF7,0x14,0x54,0x94,0x14,0xF4,0x04,0x00,0x00,0x04,0x04,0x7C,0x03,0x00,0x01,0x1D,0x13,0x11,0x55,0x99,0x51,0x3F,0x11,0x01,0x00,/*"海",32*/
	"南",0x04,0xE4,0x24,0x24,0x64,0xA4,0x24,0x3F,0x24,0xA4,0x64,0x24,0x24,0xE4,0x04,0x00,0x00,0xFF,0x00,0x08,0x09,0x09,0x09,0x7F,0x09,0x09,0x09,0x48,0x80,0x7F,0x00,0x00,/*"南",33*/
	"琼",0x44,0x44,0xFC,0x44,0x44,0x00,0x04,0xE4,0x24,0x25,0x26,0x24,0x24,0xE4,0x04,0x00,0x10,0x30,0x1F,0x08,0x08,0x20,0x10,0x0D,0x41,0x81,0x7F,0x01,0x05,0x09,0x30,0x00,/*"琼",34*/
	"四",0x00,0xFC,0x04,0x04,0x04,0xFC,0x04,0x04,0x04,0xFC,0x04,0x04,0x04,0xFC,0x00,0x00,0x00,0x7F,0x28,0x24,0x23,0x20,0x20,0x20,0x20,0x21,0x22,0x22,0x22,0x7F,0x00,0x00,/*"四",36*/
	"川",0x00,0x00,0x00,0xFF,0x00,0x00,0x00,0x00,0xFE,0x00,0x00,0x00,0x00,0xFF,0x00,0x00,0x80,0x40,0x30,0x0F,0x00,0x00,0x00,0x00,0x3F,0x00,0x00,0x00,0x00,0xFF,0x00,0x00,/*"川",37*/
	"蜀",0x00,0x00,0x9E,0x72,0x52,0x5E,0xD2,0x52,0x52,0x5E,0x52,0x52,0x5E,0xC0,0x00,0x00,0x02,0x41,0xC0,0x4F,0x49,0x49,0x3F,0x29,0x29,0x2F,0x30,0x60,0x80,0x7F,0x00,0x00,/*"蜀",38*/
	"贵",0x40,0x40,0x40,0x5E,0x52,0x52,0x52,0x7F,0x52,0x52,0x52,0x5E,0x40,0x40,0x40,0x00,0x00,0x80,0x80,0x9F,0x41,0x41,0x21,0x1D,0x01,0x21,0x21,0x5F,0x40,0x80,0x00,0x00,/*"贵",0*/
	"州",0x00,0xE0,0x00,0xFF,0x00,0x20,0xC0,0x00,0xFE,0x00,0x20,0xC0,0x00,0xFF,0x00,0x00,0x81,0x40,0x30,0x0F,0x00,0x00,0x00,0x00,0x3F,0x00,0x00,0x00,0x00,0xFF,0x00,0x00,/*"州",1*/
	"黔",0x7E,0x4A,0x52,0xFE,0x52,0x4A,0xFE,0x40,0x20,0x58,0x87,0x18,0x20,0x40,0x80,0x00,0xE9,0x09,0x69,0x07,0x65,0x05,0x35,0x00,0x02,0x02,0xC3,0x32,0x0E,0x00,0x00,0x00,/*"黔",2*/
	"云",0x40,0x40,0x42,0x42,0x42,0x42,0xC2,0x42,0x42,0x42,0x42,0x42,0x42,0x40,0x40,0x00,0x00,0x20,0x70,0x28,0x24,0x23,0x20,0x20,0x20,0x24,0x28,0x30,0xE0,0x00,0x00,0x00,/*"云",4*/
	"南",0x04,0xE4,0x24,0x24,0x64,0xA4,0x24,0x3F,0x24,0xA4,0x64,0x24,0x24,0xE4,0x04,0x00,0x00,0xFF,0x00,0x08,0x09,0x09,0x09,0x7F,0x09,0x09,0x09,0x48,0x80,0x7F,0x00,0x00,/*"南",5*/
	"滇",0x10,0x60,0x02,0x8C,0x00,0x04,0xF4,0x54,0x54,0x5F,0x54,0x54,0xF4,0x04,0x00,0x00,0x04,0x04,0x7E,0x01,0x10,0x90,0x5F,0x35,0x15,0x15,0x15,0x35,0x5F,0x90,0x10,0x00,/*"滇",7*/
	"陕",0x00,0xFE,0x22,0x5A,0x86,0x08,0x28,0x48,0x08,0xFF,0x08,0x48,0x28,0x08,0x00,0x00,0x00,0xFF,0x04,0x08,0x87,0x41,0x21,0x19,0x07,0x01,0x07,0x19,0x21,0x41,0x81,0x00,/*"陕",9*/
	"西",0x02,0x02,0xE2,0x22,0x22,0xFE,0x22,0x22,0x22,0xFE,0x22,0x22,0xE2,0x02,0x02,0x00,0x00,0x00,0xFF,0x48,0x44,0x43,0x40,0x40,0x40,0x43,0x44,0x44,0xFF,0x00,0x00,0x00,/*"西",10*/
	"陕",0x00,0xFE,0x22,0x5A,0x86,0x08,0x28,0x48,0x08,0xFF,0x08,0x48,0x28,0x08,0x00,0x00,0x00,0xFF,0x04,0x08,0x87,0x41,0x21,0x19,0x07,0x01,0x07,0x19,0x21,0x41,0x81,0x00,/*"陕",11*/
	"秦",0x20,0x22,0x2A,0xAA,0x6A,0x2A,0x3A,0x2F,0xAA,0xAA,0x6A,0xAA,0x2A,0x22,0x20,0x00,0x02,0x42,0x41,0x24,0x15,0x0D,0x05,0xFF,0x04,0x0C,0x14,0x24,0x41,0x02,0x02,0x00,/*"秦",12*/
	"甘",0x00,0x10,0x10,0x10,0xFF,0x10,0x10,0x10,0x10,0x10,0x10,0xFF,0x10,0x10,0x10,0x00,0x00,0x00,0x00,0x00,0xFF,0x42,0x42,0x42,0x42,0x42,0x42,0xFF,0x00,0x00,0x00,0x00,/*"甘",14*/
	"肃",0x10,0x10,0x54,0x54,0x54,0x54,0x54,0xFF,0x54,0x54,0x54,0x54,0x7C,0x10,0x10,0x00,0x80,0x60,0x1F,0x00,0x10,0x0E,0x00,0xFF,0x00,0x02,0x1C,0x00,0xFF,0x00,0x00,0x00,/*"肃",15*/
	"甘",0x00,0x10,0x10,0x10,0xFF,0x10,0x10,0x10,0x10,0x10,0x10,0xFF,0x10,0x10,0x10,0x00,0x00,0x00,0x00,0x00,0xFF,0x42,0x42,0x42,0x42,0x42,0x42,0xFF,0x00,0x00,0x00,0x00,/*"甘",16*/
	"陇",0x00,0xFE,0x02,0x22,0xDA,0x06,0x10,0x10,0xFF,0x10,0xF0,0x11,0x16,0x90,0x10,0x00,0x00,0xFF,0x08,0x10,0x88,0x47,0x30,0x0E,0x41,0x20,0x3F,0x48,0x46,0x41,0x78,0x00,/*"陇",17*/
	"青",0x40,0x44,0x54,0x54,0x54,0x54,0x54,0x7F,0x54,0x54,0x54,0x54,0x54,0x44,0x40,0x00,0x00,0x00,0x00,0xFF,0x15,0x15,0x15,0x15,0x15,0x55,0x95,0x7F,0x00,0x00,0x00,0x00,/*"青",19*/
	"海",0x10,0x60,0x02,0x0C,0xC0,0x10,0x08,0xF7,0x14,0x54,0x94,0x14,0xF4,0x04,0x00,0x00,0x04,0x04,0x7C,0x03,0x00,0x01,0x1D,0x13,0x11,0x55,0x99,0x51,0x3F,0x11,0x01,0x00,/*"海",20*/
	"青",0x40,0x44,0x54,0x54,0x54,0x54,0x54,0x7F,0x54,0x54,0x54,0x54,0x54,0x44,0x40,0x00,0x00,0x00,0x00,0xFF,0x15,0x15,0x15,0x15,0x15,0x55,0x95,0x7F,0x00,0x00,0x00,0x00,/*"青",21*/
	"台",0x00,0x40,0xE0,0x50,0x48,0x44,0x43,0x40,0x40,0x40,0x48,0x50,0x60,0xC0,0x00,0x00,0x00,0x00,0x00,0xFE,0x42,0x42,0x42,0x42,0x42,0x42,0x42,0xFE,0x00,0x00,0x00,0x00,/*"台",23*/
	"湾",0x10,0x60,0x02,0x8C,0x24,0x94,0x84,0xBD,0x86,0x84,0xBC,0x84,0x14,0x24,0x00,0x00,0x04,0x04,0x7E,0x01,0x00,0x0E,0x0A,0x0A,0x0A,0x4A,0x8A,0x4B,0x38,0x00,0x00,0x00,/*"湾",24*/
	"台",0x00,0x40,0xE0,0x50,0x48,0x44,0x43,0x40,0x40,0x40,0x48,0x50,0x60,0xC0,0x00,0x00,0x00,0x00,0x00,0xFE,0x42,0x42,0x42,0x42,0x42,0x42,0x42,0xFE,0x00,0x00,0x00,0x00,/*"台",25*/
	"内",0x00,0xF8,0x08,0x08,0x08,0x08,0x88,0x7F,0x88,0x08,0x08,0x08,0x08,0xF8,0x00,0x00,0x00,0xFF,0x00,0x08,0x04,0x02,0x01,0x00,0x00,0x01,0x02,0x4C,0x80,0x7F,0x00,0x00,/*"内",0*/
	"蒙",0x22,0x9A,0x8A,0x8A,0xAF,0xAA,0xAA,0xAA,0xAA,0xAA,0xAF,0x8A,0x8A,0xAA,0x1A,0x00,0x00,0x50,0x52,0x4A,0x2A,0x25,0x53,0x8A,0x7C,0x08,0x14,0x24,0x22,0x40,0x40,0x00,/*"蒙",1*/
	"古",0x10,0x10,0x10,0x10,0x10,0x10,0x10,0xFF,0x10,0x10,0x10,0x10,0x10,0x10,0x10,0x00,0x00,0x00,0x00,0xFF,0x41,0x41,0x41,0x41,0x41,0x41,0x41,0xFF,0x00,0x00,0x00,0x00,/*"古",2*/
	"自",0x00,0x00,0x00,0xF8,0x88,0x8C,0x8A,0x89,0x88,0x88,0x88,0xF8,0x00,0x00,0x00,0x00,0x00,0x00,0x00,0xFF,0x44,0x44,0x44,0x44,0x44,0x44,0x44,0xFF,0x00,0x00,0x00,0x00,/*"自",3*/
	"治",0x10,0x60,0x02,0x8C,0x00,0x20,0x30,0x28,0x24,0x23,0x20,0x28,0x30,0x60,0x00,0x00,0x04,0x04,0x7E,0x01,0x00,0x00,0xFF,0x41,0x41,0x41,0x41,0x41,0xFF,0x00,0x00,0x00,/*"治",4*/
	"区",0x00,0xFE,0x02,0x02,0x02,0x12,0x22,0x42,0x82,0x42,0x22,0x1A,0x02,0x02,0x00,0x00,0x00,0x7F,0x40,0x40,0x48,0x44,0x42,0x41,0x40,0x41,0x42,0x4C,0x40,0x40,0x40,0x00,/*"区",5*/
	"内",0x00,0xF8,0x08,0x08,0x08,0x08,0x88,0x7F,0x88,0x08,0x08,0x08,0x08,0xF8,0x00,0x00,0x00,0xFF,0x00,0x08,0x04,0x02,0x01,0x00,0x00,0x01,0x02,0x4C,0x80,0x7F,0x00,0x00,/*"内",6*/
	"蒙",0x22,0x9A,0x8A,0x8A,0xAF,0xAA,0xAA,0xAA,0xAA,0xAA,0xAF,0x8A,0x8A,0xAA,0x1A,0x00,0x00,0x50,0x52,0x4A,0x2A,0x25,0x53,0x8A,0x7C,0x08,0x14,0x24,0x22,0x40,0x40,0x00,/*"蒙",7*/
	"古",0x10,0x10,0x10,0x10,0x10,0x10,0x10,0xFF,0x10,0x10,0x10,0x10,0x10,0x10,0x10,0x00,0x00,0x00,0x00,0xFF,0x41,0x41,0x41,0x41,0x41,0x41,0x41,0xFF,0x00,0x00,0x00,0x00,/*"古",8*/
	"广",0x00,0x00,0xF8,0x08,0x08,0x08,0x08,0x09,0x0E,0x08,0x08,0x08,0x08,0x08,0x00,0x00,0x80,0x60,0x1F,0x00,0x00,0x00,0x00,0x00,0x00,0x00,0x00,0x00,0x00,0x00,0x00,0x00,/*"广",10*/
	"西",0x02,0x02,0xE2,0x22,0x22,0xFE,0x22,0x22,0x22,0xFE,0x22,0x22,0xE2,0x02,0x02,0x00,0x00,0x00,0xFF,0x48,0x44,0x43,0x40,0x40,0x40,0x43,0x44,0x44,0xFF,0x00,0x00,0x00,/*"西",11*/
	"壮",0x00,0x08,0x30,0x80,0xFF,0x00,0x40,0x40,0x40,0x40,0xFF,0x40,0x40,0x40,0x40,0x00,0x04,0x02,0x01,0x00,0xFF,0x00,0x00,0x40,0x40,0x40,0x7F,0x40,0x40,0x40,0x00,0x00,/*"壮",12*/
	"族",0x10,0x10,0xF1,0x96,0x90,0x90,0x10,0x08,0xF7,0x44,0xC4,0x44,0x44,0x44,0x04,0x00,0x80,0x60,0x1F,0x40,0x80,0x7F,0x04,0x85,0x44,0x34,0x0F,0x34,0x44,0x84,0x84,0x00,/*"族",13*/
	"自",0x00,0x00,0x00,0xF8,0x88,0x8C,0x8A,0x89,0x88,0x88,0x88,0xF8,0x00,0x00,0x00,0x00,0x00,0x00,0x00,0xFF,0x44,0x44,0x44,0x44,0x44,0x44,0x44,0xFF,0x00,0x00,0x00,0x00,/*"自",14*/
	"治",0x10,0x60,0x02,0x8C,0x00,0x20,0x30,0x28,0x24,0x23,0x20,0x28,0x30,0x60,0x00,0x00,0x04,0x04,0x7E,0x01,0x00,0x00,0xFF,0x41,0x41,0x41,0x41,0x41,0xFF,0x00,0x00,0x00,/*"治",15*/
	"区",0x00,0xFE,0x02,0x02,0x02,0x12,0x22,0x42,0x82,0x42,0x22,0x1A,0x02,0x02,0x00,0x00,0x00,0x7F,0x40,0x40,0x48,0x44,0x42,0x41,0x40,0x41,0x42,0x4C,0x40,0x40,0x40,0x00,/*"区",16*/
	"桂",0x10,0x10,0xD0,0xFF,0x90,0x10,0x40,0x44,0x44,0x44,0x7F,0x44,0x44,0x44,0x40,0x00,0x04,0x03,0x00,0xFF,0x00,0x03,0x40,0x44,0x44,0x44,0x7F,0x44,0x44,0x44,0x40,0x00,/*"桂",17*/
	"西",0x02,0x02,0xE2,0x22,0x22,0xFE,0x22,0x22,0x22,0xFE,0x22,0x22,0xE2,0x02,0x02,0x00,0x00,0x00,0xFF,0x48,0x44,0x43,0x40,0x40,0x40,0x43,0x44,0x44,0xFF,0x00,0x00,0x00,/*"西",19*/
	"藏",0x02,0xE2,0x82,0xF2,0x12,0xD7,0x52,0xD2,0x52,0x17,0xFA,0x12,0x16,0x9A,0x12,0x00,0x12,0x8E,0x62,0x1F,0x00,0x3F,0x25,0x3D,0xA7,0x40,0x27,0x18,0x26,0x41,0xF0,0x00,/*"藏",20*/
	"自",0x00,0x00,0x00,0xF8,0x88,0x8C,0x8A,0x89,0x88,0x88,0x88,0xF8,0x00,0x00,0x00,0x00,0x00,0x00,0x00,0xFF,0x44,0x44,0x44,0x44,0x44,0x44,0x44,0xFF,0x00,0x00,0x00,0x00,/*"自",21*/
	"治",0x10,0x60,0x02,0x8C,0x00,0x20,0x30,0x28,0x24,0x23,0x20,0x28,0x30,0x60,0x00,0x00,0x04,0x04,0x7E,0x01,0x00,0x00,0xFF,0x41,0x41,0x41,0x41,0x41,0xFF,0x00,0x00,0x00,/*"治",22*/
	"区",0x00,0xFE,0x02,0x02,0x02,0x12,0x22,0x42,0x82,0x42,0x22,0x1A,0x02,0x02,0x00,0x00,0x00,0x7F,0x40,0x40,0x48,0x44,0x42,0x41,0x40,0x41,0x42,0x4C,0x40,0x40,0x40,0x00,/*"区",23*/
	"藏",0x02,0xE2,0x82,0xF2,0x12,0xD7,0x52,0xD2,0x52,0x17,0xFA,0x12,0x16,0x9A,0x12,0x00,0x12,0x8E,0x62,0x1F,0x00,0x3F,0x25,0x3D,0xA7,0x40,0x27,0x18,0x26,0x41,0xF0,0x00,/*"藏",24*/
	"宁",0x20,0x18,0x88,0x88,0x88,0x88,0x89,0x8E,0x88,0x88,0x88,0x88,0x88,0x28,0x18,0x00,0x00,0x00,0x00,0x00,0x00,0x40,0x80,0x7F,0x00,0x00,0x00,0x00,0x00,0x00,0x00,0x00,/*"宁",26*/
	"夏",0x00,0x01,0x01,0xFD,0x55,0x55,0x57,0x55,0x55,0x55,0x55,0xFD,0x01,0x01,0x00,0x00,0x80,0x90,0x88,0x45,0x4F,0x55,0x25,0x25,0x25,0x55,0x4D,0x45,0x80,0x80,0x80,0x00,/*"夏",27*/
	"回",0x00,0x00,0xFE,0x02,0x02,0xF2,0x12,0x12,0x12,0xF2,0x02,0x02,0xFE,0x00,0x00,0x00,0x00,0x00,0x7F,0x20,0x20,0x27,0x24,0x24,0x24,0x27,0x20,0x20,0x7F,0x00,0x00,0x00,/*"回",28*/
	"族",0x10,0x10,0xF1,0x96,0x90,0x90,0x10,0x08,0xF7,0x44,0xC4,0x44,0x44,0x44,0x04,0x00,0x80,0x60,0x1F,0x40,0x80,0x7F,0x04,0x85,0x44,0x34,0x0F,0x34,0x44,0x84,0x84,0x00,/*"族",29*/
	"自",0x00,0x00,0x00,0xF8,0x88,0x8C,0x8A,0x89,0x88,0x88,0x88,0xF8,0x00,0x00,0x00,0x00,0x00,0x00,0x00,0xFF,0x44,0x44,0x44,0x44,0x44,0x44,0x44,0xFF,0x00,0x00,0x00,0x00,/*"自",30*/
	"治",0x10,0x60,0x02,0x8C,0x00,0x20,0x30,0x28,0x24,0x23,0x20,0x28,0x30,0x60,0x00,0x00,0x04,0x04,0x7E,0x01,0x00,0x00,0xFF,0x41,0x41,0x41,0x41,0x41,0xFF,0x00,0x00,0x00,/*"治",31*/
	"区",0x00,0xFE,0x02,0x02,0x02,0x12,0x22,0x42,0x82,0x42,0x22,0x1A,0x02,0x02,0x00,0x00,0x00,0x7F,0x40,0x40,0x48,0x44,0x42,0x41,0x40,0x41,0x42,0x4C,0x40,0x40,0x40,0x00,/*"区",32*/
	"宁",0x20,0x18,0x88,0x88,0x88,0x88,0x89,0x8E,0x88,0x88,0x88,0x88,0x88,0x28,0x18,0x00,0x00,0x00,0x00,0x00,0x00,0x40,0x80,0x7F,0x00,0x00,0x00,0x00,0x00,0x00,0x00,0x00,/*"宁",33*/
	"新",0x40,0x44,0x54,0x65,0xC6,0x64,0x54,0x44,0x00,0xFC,0x44,0x44,0xC4,0x42,0x40,0x00,0x20,0x12,0x4A,0x82,0x7F,0x02,0x0A,0x92,0x60,0x1F,0x00,0x00,0xFF,0x00,0x00,0x00,/*"新",35*/
	"疆",0xF2,0x92,0x92,0x92,0x9E,0x00,0x82,0xFA,0xAA,0xAA,0xFA,0xAA,0xAA,0xFA,0x82,0x00,0x24,0x5F,0x94,0x40,0x3F,0x00,0x80,0xBE,0xAA,0xAA,0xBE,0xAA,0xAA,0xBE,0x80,0x00,/*"疆",36*/
	"维",0x20,0x30,0xAC,0x63,0x20,0x58,0x20,0xF8,0x4F,0x48,0x49,0xFA,0x48,0x48,0x08,0x00,0x22,0x67,0x22,0x12,0x12,0x12,0x00,0xFF,0x22,0x22,0x22,0x3F,0x22,0x22,0x20,0x00,/*"维",37*/
	"吾",0x00,0x02,0x12,0x12,0x92,0x72,0x1E,0x12,0x12,0x12,0x12,0xF2,0x02,0x02,0x00,0x00,0x01,0x01,0x01,0xFD,0x45,0x45,0x45,0x45,0x45,0x45,0x45,0xFD,0x01,0x01,0x01,0x00,/*"吾",38*/
	"尔",0x80,0x40,0x20,0x18,0x0F,0x08,0x08,0xE8,0x08,0x08,0x08,0x08,0x28,0x18,0x00,0x00,0x20,0x10,0x08,0x06,0x00,0x40,0x80,0x7F,0x00,0x00,0x00,0x02,0x04,0x08,0x30,0x00,/*"尔",39*/
	"自",0x00,0x00,0x00,0xF8,0x88,0x8C,0x8A,0x89,0x88,0x88,0x88,0xF8,0x00,0x00,0x00,0x00,0x00,0x00,0x00,0xFF,0x44,0x44,0x44,0x44,0x44,0x44,0x44,0xFF,0x00,0x00,0x00,0x00,/*"自",40*/
	"治",0x10,0x60,0x02,0x8C,0x00,0x20,0x30,0x28,0x24,0x23,0x20,0x28,0x30,0x60,0x00,0x00,0x04,0x04,0x7E,0x01,0x00,0x00,0xFF,0x41,0x41,0x41,0x41,0x41,0xFF,0x00,0x00,0x00,/*"治",41*/
	"区",0x00,0xFE,0x02,0x02,0x02,0x12,0x22,0x42,0x82,0x42,0x22,0x1A,0x02,0x02,0x00,0x00,0x00,0x7F,0x40,0x40,0x48,0x44,0x42,0x41,0x40,0x41,0x42,0x4C,0x40,0x40,0x40,0x00,/*"区",42*/
	"新",0x40,0x44,0x54,0x65,0xC6,0x64,0x54,0x44,0x00,0xFC,0x44,0x44,0xC4,0x42,0x40,0x00,0x20,0x12,0x4A,0x82,0x7F,0x02,0x0A,0x92,0x60,0x1F,0x00,0x00,0xFF,0x00,0x00,0x00,/*"新",43*/
	"北",0x00,0x20,0x20,0x20,0x20,0xFF,0x00,0x00,0x00,0xFF,0x40,0x20,0x10,0x08,0x00,0x00,0x20,0x60,0x20,0x10,0x10,0xFF,0x00,0x00,0x00,0x3F,0x40,0x40,0x40,0x40,0x78,0x00,/*"北",0*/
	"京",0x04,0x04,0x04,0xE4,0x24,0x24,0x25,0x26,0x24,0x24,0x24,0xE4,0x04,0x04,0x04,0x00,0x00,0x40,0x20,0x1B,0x02,0x42,0x82,0x7E,0x02,0x02,0x02,0x0B,0x10,0x60,0x00,0x00,/*"京",1*/
	"市",0x00,0x08,0x88,0x88,0x88,0x88,0x89,0xFA,0x88,0x88,0x88,0x88,0x88,0x08,0x00,0x00,0x00,0x00,0x3F,0x00,0x00,0x00,0x00,0xFF,0x00,0x00,0x10,0x20,0x1F,0x00,0x00,0x00,/*"市",2*/
	"上",0x00,0x00,0x00,0x00,0x00,0x00,0xFF,0x40,0x40,0x40,0x40,0x40,0x40,0x00,0x00,0x00,0x40,0x40,0x40,0x40,0x40,0x40,0x7F,0x40,0x40,0x40,0x40,0x40,0x40,0x40,0x40,0x00,/*"上",5*/
	"海",0x10,0x60,0x02,0x0C,0xC0,0x10,0x08,0xF7,0x14,0x54,0x94,0x14,0xF4,0x04,0x00,0x00,0x04,0x04,0x7C,0x03,0x00,0x01,0x1D,0x13,0x11,0x55,0x99,0x51,0x3F,0x11,0x01,0x00,/*"海",6*/
	"沪",0x10,0x60,0x02,0x8C,0x00,0x00,0xF8,0x88,0x89,0x8E,0x88,0x88,0x88,0xF8,0x00,0x00,0x04,0x04,0x7E,0x81,0x40,0x30,0x0F,0x00,0x00,0x00,0x00,0x00,0x00,0x01,0x00,0x00,/*"沪",8*/
	"天",0x40,0x40,0x42,0x42,0x42,0x42,0x42,0xFE,0x42,0x42,0x42,0x42,0x42,0x40,0x40,0x00,0x80,0x80,0x40,0x20,0x10,0x0C,0x03,0x00,0x03,0x0C,0x10,0x20,0x40,0x80,0x80,0x00,/*"天",10*/
	"津",0x10,0x60,0x02,0x0C,0xC0,0x10,0x54,0x54,0x54,0xFF,0x54,0x54,0x7C,0x10,0x10,0x00,0x04,0x04,0x7C,0x03,0x00,0x10,0x12,0x12,0x12,0xFF,0x12,0x12,0x12,0x10,0x00,0x00,/*"津",11*/
	"重",0x10,0x10,0x14,0xD4,0x54,0x54,0x54,0xFC,0x52,0x52,0x52,0xD3,0x12,0x10,0x10,0x00,0x40,0x40,0x50,0x57,0x55,0x55,0x55,0x7F,0x55,0x55,0x55,0x57,0x50,0x40,0x40,0x00,/*"重",15*/
	"庆",0x00,0x00,0xFC,0x04,0x84,0x84,0x84,0x85,0xF6,0x84,0x84,0x84,0x84,0x84,0x04,0x00,0x40,0x30,0x0F,0x80,0x40,0x20,0x18,0x06,0x01,0x06,0x18,0x20,0x40,0x80,0x80,0x00,/*"庆",16*/
	"渝",0x10,0x60,0x02,0x8C,0x20,0xD0,0x48,0x54,0x52,0xD1,0x12,0x94,0x08,0xD0,0x10,0x00,0x04,0x04,0x7E,0x01,0x00,0xFF,0x12,0x52,0x92,0x7F,0x00,0x5F,0x80,0x7F,0x00,0x00,/*"渝",18*/
	"香",0x10,0x10,0x90,0x92,0x52,0x32,0x12,0xFE,0x12,0x31,0x51,0x91,0x90,0x10,0x10,0x00,0x01,0x01,0x00,0xFF,0x49,0x49,0x49,0x49,0x49,0x49,0x49,0xFF,0x00,0x01,0x01,0x00,/*"香",0*/
	"港",0x10,0x60,0x02,0x8C,0x20,0x24,0xA4,0x7F,0x24,0x24,0x24,0x7F,0xA4,0x24,0x20,0x00,0x04,0x04,0x7E,0x01,0x02,0x01,0x3F,0x49,0x49,0x49,0x49,0x4F,0x40,0x71,0x02,0x00,/*"港",1*/
	"特",0x40,0x3C,0x10,0xFF,0x10,0x10,0x40,0x48,0x48,0x48,0x7F,0x48,0xC8,0x48,0x40,0x00,0x02,0x06,0x02,0xFF,0x01,0x01,0x00,0x02,0x0A,0x12,0x42,0x82,0x7F,0x02,0x02,0x00,/*"特",2*/
	"别",0x00,0x3E,0x22,0xE2,0x22,0x22,0x22,0x3E,0x00,0x00,0xF8,0x00,0x00,0xFF,0x00,0x00,0x81,0x41,0x31,0x0F,0x41,0x81,0x41,0x3F,0x00,0x00,0x0F,0x40,0x80,0x7F,0x00,0x00,/*"别",3*/
	"行",0x00,0x10,0x88,0xC4,0x33,0x00,0x40,0x42,0x42,0x42,0xC2,0x42,0x42,0x42,0x40,0x00,0x02,0x01,0x00,0xFF,0x00,0x00,0x00,0x00,0x40,0x80,0x7F,0x00,0x00,0x00,0x00,0x00,/*"行",4*/
	"政",0x04,0xC4,0x04,0x04,0xFC,0x84,0x84,0x04,0x80,0x70,0x8F,0x08,0x08,0xF8,0x08,0x00,0x20,0x3F,0x20,0x20,0x1F,0x10,0x10,0x90,0x40,0x20,0x13,0x0C,0x33,0x40,0x80,0x00,/*"政",5*/
	"区",0x00,0xFE,0x02,0x02,0x02,0x12,0x22,0x42,0x82,0x42,0x22,0x1A,0x02,0x02,0x00,0x00,0x00,0x7F,0x40,0x40,0x48,0x44,0x42,0x41,0x40,0x41,0x42,0x4C,0x40,0x40,0x40,0x00,/*"区",6*/
	"港",0x10,0x60,0x02,0x8C,0x20,0x24,0xA4,0x7F,0x24,0x24,0x24,0x7F,0xA4,0x24,0x20,0x00,0x04,0x04,0x7E,0x01,0x02,0x01,0x3F,0x49,0x49,0x49,0x49,0x4F,0x40,0x71,0x02,0x00,
	"澳",0x10,0x60,0x02,0x8C,0x00,0xFC,0x44,0x56,0xC5,0xFC,0xC4,0x54,0x44,0xFC,0x00,0x00,0x04,0x04,0x7E,0x01,0x88,0x8B,0x48,0x29,0x18,0x0D,0x18,0x29,0x48,0x8B,0x88,0x00,
	"门",0x00,0xF8,0x01,0x06,0x00,0x00,0x02,0x02,0x02,0x02,0x02,0x02,0x02,0xFE,0x00,0x00,0x00,0xFF,0x00,0x00,0x00,0x00,0x00,0x00,0x00,0x00,0x00,0x40,0x80,0x7F,0x00,0x00,
	"澳",0x10,0x60,0x02,0x8C,0x00,0xFC,0x44,0x56,0xC5,0xFC,0xC4,0x54,0x44,0xFC,0x00,0x00,0x04,0x04,0x7E,0x01,0x88,0x8B,0x48,0x29,0x18,0x0D,0x18,0x29,0x48,0x8B,0x88,0x00,

};

/**
  * @brief  OLED显示汉字
  * @param  Row 起始行位置，范围：1~4
  * @param  Column 起始列位置，范围：1~16
  * @param  CH 要显示的数字，范围：前文OLED_F16x16内部定义的汉字
  * @retval 无
  */
void OLED_ShowChinese(uint8_t Row, uint8_t Column, char *CH)
{
	uint8_t i,j,k,n = 0;
	char *p = CH;
	while (*p++ != '\0')
	{
		n ++;
	}
	for(k = 0; k < n; k +=3)
	{
		for(i = 0; i < sizeof(OLED_F16x16)/sizeof(GB16); i ++)
		{
			if((OLED_F16x16[i].Index[0] == CH[k]) && (OLED_F16x16[i].Index[1] == CH[k+1]) && (OLED_F16x16[i].Index[2] == CH[k+2]))
			{
				OLED_SetCursor((Row - 1) * 2, (Column - 1) * 8 + 8 * 2*k/3);			//设置光标位置在上半部分
				for (j = 0; j < 16; j ++)
				{
					OLED_WriteData(OLED_F16x16[i].Mask[j]);													//显示上半部分内容
				}
				OLED_SetCursor((Row - 1) * 2 + 1, (Column - 1) * 8 + 8 * 2*k/3);	//设置光标位置在下半部分
				for (j = 0; j < 16; j ++)
				{
					OLED_WriteData(OLED_F16x16[i].Mask[j + 16]);										//显示下半部分内容
				}
			}
		}
	}
}

/**
  * @brief  OLED次方函数
  * @retval 返回值等于X的Y次方
  */
uint32_t OLED_Pow(uint32_t X, uint32_t Y)
{
	uint32_t Result = 1;
	while (Y--)
	{
		Result *= X;
	}
	return Result;
}

/**
  * @brief  OLED显示数字（十进制，正数）
  * @param  Row 起始行位置，范围：1~4
  * @param  Column 起始列位置，范围：1~16
  * @param  Integer 要显示的数字，范围：0~4294967295
  * @param  Length 要显示数字的长度，范围：1~10
  * @retval 无
  */
void OLED_ShowInteger(uint8_t Row, uint8_t Column, uint32_t Integer, uint8_t Length)
{
	uint8_t i;
	for (i = 0; i < Length; i++)
	{
		OLED_ShowCharacter(Row, Column + i, Integer / OLED_Pow(10, Length - i - 1) % 10 + '0');
	}
}

/**
  * @brief  OLED显示数字（十进制，带符号数）
  * @param  Row 起始行位置，范围：1~4
  * @param  Column 起始列位置，范围：1~16
  * @param  Integer 要显示的数字，范围：-2147483648~2147483647
  * @param  Length 要显示数字的长度，范围：1~10
  * @retval 无
  */
void OLED_ShowSignedInteger(uint8_t Row, uint8_t Column, int32_t Integer, uint8_t Length)
{
	uint8_t i;
	uint32_t Integer1;
	if (Integer >= 0)
	{
		OLED_ShowCharacter(Row, Column, '+');
		Integer1 = Integer;
	}
	else
	{
		OLED_ShowCharacter(Row, Column, '-');
		Integer1 = -Integer;
	}
	for (i = 0; i < Length; i++)
	{
		OLED_ShowCharacter(Row, Column + i + 1, Integer1 / OLED_Pow(10, Length - i - 1) % 10 + '0');
	}
}

/**
  * @brief  OLED显示数字（十六进制，正数）
  * @param  Row 起始行位置，范围：1~4
  * @param  Column 起始列位置，范围：1~16
  * @param  Integer 要显示的数字，范围：0~0xFFFFFFFF
  * @param  Length 要显示数字的长度，范围：1~8
  * @retval 无
  */
void OLED_ShowHexInteger(uint8_t Row, uint8_t Column, uint32_t Integer, uint8_t Length)
{
	uint8_t i,SingleInteger;
	OLED_ShowCharacter(Row, Column + 0, '0');
	OLED_ShowCharacter(Row, Column + 1, 'x');
	for (i = 0; i < Length; i++)
	{
		SingleInteger = Integer / OLED_Pow(16, Length - i - 1) % 16;
		if (SingleInteger < 10)
		{
			OLED_ShowCharacter(Row, Column + i + 2, SingleInteger + '0');
		}
		else
		{
			OLED_ShowCharacter(Row, Column + i + 2, SingleInteger - 10 + 'A');
		}
	}
}

/**
  * @brief  OLED显示数字（二进制，正数）
  * @param  Row 起始行位置，范围：1~4
  * @param  Column 起始列位置，范围：1~16
  * @param  Integer 要显示的数字，范围：0~1111 1111 1111 1111
  * @param  Length 要显示数字的长度，范围：1~16
  * @retval 无
  */
void OLED_ShowBinInteger(uint8_t Row, uint8_t Column, uint32_t Integer, uint8_t Length)
{
	uint8_t i;
	for (i = 0; i < Length; i++)
	{
		OLED_ShowCharacter(Row, Column + i, Integer / OLED_Pow(2, Length - i - 1) % 2 + '0');
	}
}

/**
  * @brief  OLED显示无符号浮点数
  * @param  Row 起始行位置，范围：1~4
  * @param  Column 起始列位置，范围：1~16
  * @param  Number 要显示的数字，范围：0~+999.99
  * @param  LengthOfIntegralPart 要显示整数部分的长度，范围：3~1
  * @param  LengthOfDecimalPart 要显示小数部分的长度，范围：0~2
  * @retval 无
  */
void OLED_ShowUnsignedFloat(uint8_t Row, uint8_t Column, float Number, uint8_t LengthOfIntegralPart, uint8_t LengthOfDecimalPart)
{
	uint32_t i2,i1,i0,f1,f2;
	i2 = (uint32_t)Number % 1000 / 100;						//求百位
	i1 = (uint32_t)Number % 100 / 10;						//求十位
	i0 = (uint32_t)Number % 10 / 1;   						//求个位
	f1 = ((Number-(uint32_t)Number))*10;					//求小数点后一位
	f2 = (uint32_t)((Number-(uint32_t)Number)*100)%10;		//求小数点后两位

	if(LengthOfIntegralPart == 1)
	{
		if(LengthOfDecimalPart == 0)
		{
			OLED_ShowInteger(Row, Column + 0, i0 ,1);
		}
		else if(LengthOfDecimalPart == 1)
		{
			OLED_ShowInteger(Row, Column + 0, i0 ,1);
			OLED_ShowCharacter(Row, Column + 1, '.');
			OLED_ShowInteger(Row, Column + 2, f1 ,1);
		}
		else
		{
			OLED_ShowInteger(Row, Column + 0, i0 ,1);
			OLED_ShowCharacter(Row, Column + 1, '.');
			OLED_ShowInteger(Row, Column + 2, f1 ,1);
			OLED_ShowInteger(Row, Column + 3, f2 ,1);
		}
	}
	else if(LengthOfIntegralPart == 2)
	{
		if(LengthOfDecimalPart == 0)
		{
			OLED_ShowInteger(Row, Column + 0, i1 ,1);
			OLED_ShowInteger(Row, Column + 1, i0 ,1);
		}
		else if(LengthOfDecimalPart == 1)
		{
			OLED_ShowInteger(Row, Column + 0, i1 ,1);
			OLED_ShowInteger(Row, Column + 1, i0 ,1);
			OLED_ShowCharacter(Row, Column + 2, '.');
			OLED_ShowInteger(Row, Column + 3, f1 ,1);
		}
		else
		{
			OLED_ShowInteger(Row, Column + 0, i1 ,1);
			OLED_ShowInteger(Row, Column + 1, i0 ,1);
			OLED_ShowCharacter(Row, Column + 2, '.');
			OLED_ShowInteger(Row, Column + 3, f1 ,1);
			OLED_ShowInteger(Row, Column + 4, f2 ,1);
		}
	}
	else
	{
		if(LengthOfDecimalPart == 0)
		{
			OLED_ShowInteger(Row, Column + 0, i2 ,1);
			OLED_ShowInteger(Row, Column + 1, i1 ,1);
			OLED_ShowInteger(Row, Column + 2, i0 ,1);
		}
		else if(LengthOfDecimalPart == 1)
		{
			OLED_ShowInteger(Row, Column + 0, i2 ,1);
			OLED_ShowInteger(Row, Column + 1, i1 ,1);
			OLED_ShowInteger(Row, Column + 2, i0 ,1);
			OLED_ShowCharacter(Row, Column + 3, '.');
			OLED_ShowInteger(Row, Column + 4, f1 ,1);
		}
		else
		{
			OLED_ShowInteger(Row, Column + 0, i2 ,1);
			OLED_ShowInteger(Row, Column + 1, i1 ,1);
			OLED_ShowInteger(Row, Column + 2, i0 ,1);
			OLED_ShowCharacter(Row, Column + 3, '.');
			OLED_ShowInteger(Row, Column + 4, f1 ,1);
			OLED_ShowInteger(Row, Column + 5, f2 ,1);
		}
	}
}

/**
  * @brief  OLED显示浮点数
  * @param  Row 起始行位置，范围：1~4
  * @param  Column 起始列位置，范围：1~16
  * @param  Number 要显示的数字，范围：-999.99~+999.99
  * @param  LengthOfIntegralPart 要显示整数部分的长度，范围：3~1
  * @param  LengthOfDecimalPart 要显示小数部分的长度，范围：0~2
  * @retval 无
  */
void OLED_ShowSignedFloat(uint8_t Row, uint8_t Column, float Number, uint8_t LengthOfIntegralPart, uint8_t LengthOfDecimalPart)
{
	float AbsoluteValue = Number >= 0 ? Number : -Number;
	if(Number > 0)
	{
		OLED_ShowCharacter(Row, Column, '+');
	}
	else if(Number < 0)
	{
		OLED_ShowCharacter(Row, Column, '-');
	}
	else
	{
		OLED_ShowCharacter(Row, Column, ' ');
	}
	OLED_ShowUnsignedFloat(Row, Column+1, AbsoluteValue, LengthOfIntegralPart, LengthOfDecimalPart);
}

/**
  * @brief  OLED初始化
  * @param  无
  * @retval 无
  */
void OLED_Init(void)
{
	HAL_Delay(250);

	OLED_I2C_Init();					//端口初始化

	OLED_WriteCommand(0xAE);	//关闭显示

	OLED_WriteCommand(0xD5);	//设置显示时钟分频比/振荡器频率
	OLED_WriteCommand(0x80);

	OLED_WriteCommand(0xA8);	//设置多路复用率
	OLED_WriteCommand(0x3F);

	OLED_WriteCommand(0xD3);	//设置显示偏移
	OLED_WriteCommand(0x00);

	OLED_WriteCommand(0x40);	//设置显示开始行

	OLED_WriteCommand(0xA1);	//设置左右方向，0xA1正常 0xA0左右反置

	OLED_WriteCommand(0xC8);	//设置上下方向，0xC8正常 0xC0上下反置

	OLED_WriteCommand(0xDA);	//设置COM引脚硬件配置
	OLED_WriteCommand(0x12);

	OLED_WriteCommand(0x81);	//设置对比度控制
	OLED_WriteCommand(0xCF);

	OLED_WriteCommand(0xD9);	//设置预充电周期
	OLED_WriteCommand(0xF1);

	OLED_WriteCommand(0xDB);	//设置VCOMH取消选择级别
	OLED_WriteCommand(0x30);

	OLED_WriteCommand(0xA4);	//设置整个显示打开/关闭

	OLED_WriteCommand(0xA6);	//设置正常/倒转显示

	OLED_WriteCommand(0x8D);	//设置充电泵
	OLED_WriteCommand(0x14);

	OLED_WriteCommand(0xAF);	//开启显示

	OLED_Clear();							//OLED清屏
}

uint8_t flag=1;

/* USER CODE END 0 */

int main(void) {

  /* MCU Configuration--------------------------------------------------------*/

  /* Reset of all peripherals, Initializes the Flash interface and the Systick. */
  HAL_Init();

  /* Configure the system clock */
  SystemClock_Config();

  /* USER CODE BEGIN SysInit */
  //Delay_Init();
  /* USER CODE END SysInit */

  /* Initialize all configured peripherals */

  /* USER CODE BEGIN 2 */
  OLED_Init();
  Keys_Init();
  uint16_t counter=1;
  //uint16_t hangshu=1;

  /* USER CODE END 2 */

  /* Infinite loop */
  /* USER CODE BEGIN WHILE */
  while (1) {
    if(counter>256)counter=0;
    else counter++;
    if  (flag)
      OLED_ShowChinese(1,2,"->");
    if(KeyB1_HasBeenClicked())
    {
      flag=-1;

    }

    OLED_ShowChinese(1,4,"江苏省");
    OLED_ShowChinese(2,4,"湖北省");
    OLED_ShowChinese(3,4,"河南省");
    OLED_ShowChinese(4,4,"湖南省");
    //if(HAL_GPIO_ReadPin(GPIOB, GPIO_PIN_8));

    /* USER CODE END WHILE */

  }
}

void SystemClock_Config(void)
{
  RCC_OscInitTypeDef RCC_OscInitStruct = {0};
  RCC_ClkInitTypeDef RCC_ClkInitStruct = {0};

  /** Configure the main internal regulator output voltage
  */
  __HAL_RCC_PWR_CLK_ENABLE();
  __HAL_PWR_VOLTAGESCALING_CONFIG(PWR_REGULATOR_VOLTAGE_SCALE1);

  /** Initializes the RCC Oscillators according to the specified parameters
  * in the RCC_OscInitTypeDef structure.
  */
  RCC_OscInitStruct.OscillatorType = RCC_OSCILLATORTYPE_HSI;
  RCC_OscInitStruct.HSIState = RCC_HSI_ON;
  RCC_OscInitStruct.HSICalibrationValue = RCC_HSICALIBRATION_DEFAULT;
  RCC_OscInitStruct.PLL.PLLState = RCC_PLL_NONE;
  if (HAL_RCC_OscConfig(&RCC_OscInitStruct) != HAL_OK)
  {
    Error_Handler();
  }

  /** Initializes the CPU, AHB and APB buses clocks
  */
  RCC_ClkInitStruct.ClockType = RCC_CLOCKTYPE_HCLK|RCC_CLOCKTYPE_SYSCLK
                              |RCC_CLOCKTYPE_PCLK1|RCC_CLOCKTYPE_PCLK2;
  RCC_ClkInitStruct.SYSCLKSource = RCC_SYSCLKSOURCE_HSI;
  RCC_ClkInitStruct.AHBCLKDivider = RCC_SYSCLK_DIV1;
  RCC_ClkInitStruct.APB1CLKDivider = RCC_HCLK_DIV1;
  RCC_ClkInitStruct.APB2CLKDivider = RCC_HCLK_DIV1;

  if (HAL_RCC_ClockConfig(&RCC_ClkInitStruct, FLASH_LATENCY_0) != HAL_OK)
  {
    Error_Handler();
  }
}

void Error_Handler(void)
{
  __disable_irq();
  while (1)
  {
  }
}
